VERSION 5.7 ;
  NOWIREEXTENSIONATPIN ON ;
  DIVIDERCHAR "/" ;
  BUSBITCHARS "[]" ;
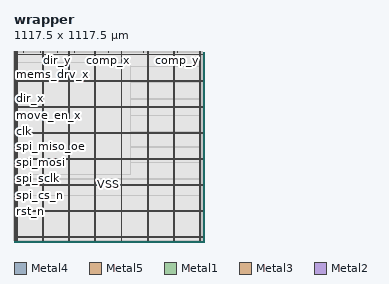
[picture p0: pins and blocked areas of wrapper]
MACRO wrapper
  CLASS BLOCK ;
  FOREIGN wrapper ;
  ORIGIN 0.000 0.000 ;
  SIZE 1117.500 BY 1117.500 ;
  PIN VDD
    DIRECTION INOUT ;
    USE POWER ;
    PORT
      LAYER Metal4 ;
        RECT 15.520 11.460 17.120 1117.500 ;
    END
    PORT
      LAYER Metal4 ;
        RECT 169.120 11.460 170.720 1117.500 ;
    END
    PORT
      LAYER Metal4 ;
        RECT 322.720 11.460 324.320 1117.500 ;
    END
    PORT
      LAYER Metal4 ;
        RECT 476.320 11.460 477.920 1117.500 ;
    END
    PORT
      LAYER Metal4 ;
        RECT 629.920 11.460 631.520 1117.500 ;
    END
    PORT
      LAYER Metal4 ;
        RECT 783.520 11.460 785.120 1117.500 ;
    END
    PORT
      LAYER Metal4 ;
        RECT 937.120 11.460 938.720 1117.500 ;
    END
    PORT
      LAYER Metal4 ;
        RECT 1090.720 11.460 1092.320 1117.500 ;
    END
    PORT
      LAYER Metal5 ;
        RECT 0.000 27.610 1107.120 29.210 ;
    END
    PORT
      LAYER Metal5 ;
        RECT 0.000 180.790 1107.120 182.390 ;
    END
    PORT
      LAYER Metal5 ;
        RECT 0.000 333.970 1107.120 335.570 ;
    END
    PORT
      LAYER Metal5 ;
        RECT 0.000 487.150 1107.120 488.750 ;
    END
    PORT
      LAYER Metal5 ;
        RECT 0.000 640.330 1107.120 641.930 ;
    END
    PORT
      LAYER Metal5 ;
        RECT 0.000 793.510 1107.120 795.110 ;
    END
    PORT
      LAYER Metal5 ;
        RECT 0.000 946.690 1107.120 948.290 ;
    END
    PORT
      LAYER Metal5 ;
        RECT 0.000 1099.870 1107.120 1101.470 ;
    END
    PORT
      LAYER Metal1 ;
        RECT 0.000 15.380 15.670 15.980 ;
    END
    PORT
      LAYER Metal1 ;
        RECT 0.000 23.220 15.670 23.820 ;
    END
    PORT
      LAYER Metal1 ;
        RECT 0.000 31.060 15.670 31.660 ;
    END
    PORT
      LAYER Metal1 ;
        RECT 0.000 38.900 15.670 39.500 ;
    END
    PORT
      LAYER Metal1 ;
        RECT 0.000 46.740 15.670 47.340 ;
    END
    PORT
      LAYER Metal1 ;
        RECT 0.000 54.580 15.670 55.180 ;
    END
    PORT
      LAYER Metal1 ;
        RECT 0.000 62.420 15.670 63.020 ;
    END
    PORT
      LAYER Metal1 ;
        RECT 0.000 70.260 15.670 70.860 ;
    END
    PORT
      LAYER Metal1 ;
        RECT 0.000 78.100 15.670 78.700 ;
    END
    PORT
      LAYER Metal1 ;
        RECT 0.000 85.940 15.670 86.540 ;
    END
    PORT
      LAYER Metal1 ;
        RECT 0.000 93.780 15.670 94.380 ;
    END
    PORT
      LAYER Metal1 ;
        RECT 0.000 101.620 15.670 102.220 ;
    END
    PORT
      LAYER Metal1 ;
        RECT 0.000 109.460 15.670 110.060 ;
    END
    PORT
      LAYER Metal1 ;
        RECT 0.000 117.300 15.670 117.900 ;
    END
    PORT
      LAYER Metal1 ;
        RECT 0.000 125.140 15.670 125.740 ;
    END
    PORT
      LAYER Metal1 ;
        RECT 0.000 132.980 15.670 133.580 ;
    END
    PORT
      LAYER Metal1 ;
        RECT 0.000 140.820 15.670 141.420 ;
    END
    PORT
      LAYER Metal1 ;
        RECT 0.000 148.660 15.670 149.260 ;
    END
    PORT
      LAYER Metal1 ;
        RECT 0.000 156.500 15.670 157.100 ;
    END
    PORT
      LAYER Metal1 ;
        RECT 0.000 164.340 15.670 164.940 ;
    END
    PORT
      LAYER Metal1 ;
        RECT 0.000 172.180 15.670 172.780 ;
    END
    PORT
      LAYER Metal1 ;
        RECT 0.000 180.020 15.670 180.620 ;
    END
    PORT
      LAYER Metal1 ;
        RECT 0.000 187.860 15.670 188.460 ;
    END
    PORT
      LAYER Metal1 ;
        RECT 0.000 195.700 15.670 196.300 ;
    END
    PORT
      LAYER Metal1 ;
        RECT 0.000 203.540 15.670 204.140 ;
    END
    PORT
      LAYER Metal1 ;
        RECT 0.000 211.380 15.670 211.980 ;
    END
    PORT
      LAYER Metal1 ;
        RECT 0.000 219.220 15.670 219.820 ;
    END
    PORT
      LAYER Metal1 ;
        RECT 0.000 227.060 15.670 227.660 ;
    END
    PORT
      LAYER Metal1 ;
        RECT 0.000 234.900 15.670 235.500 ;
    END
    PORT
      LAYER Metal1 ;
        RECT 0.000 242.740 15.670 243.340 ;
    END
    PORT
      LAYER Metal1 ;
        RECT 0.000 250.580 15.670 251.180 ;
    END
    PORT
      LAYER Metal1 ;
        RECT 0.000 258.420 15.670 259.020 ;
    END
    PORT
      LAYER Metal1 ;
        RECT 0.000 266.260 15.670 266.860 ;
    END
    PORT
      LAYER Metal1 ;
        RECT 0.000 274.100 15.670 274.700 ;
    END
    PORT
      LAYER Metal1 ;
        RECT 0.000 281.940 15.670 282.540 ;
    END
    PORT
      LAYER Metal1 ;
        RECT 0.000 289.780 15.670 290.380 ;
    END
    PORT
      LAYER Metal1 ;
        RECT 0.000 297.620 15.670 298.220 ;
    END
    PORT
      LAYER Metal1 ;
        RECT 0.000 305.460 15.670 306.060 ;
    END
    PORT
      LAYER Metal1 ;
        RECT 0.000 313.300 15.670 313.900 ;
    END
    PORT
      LAYER Metal1 ;
        RECT 0.000 321.140 15.670 321.740 ;
    END
    PORT
      LAYER Metal1 ;
        RECT 0.000 328.980 15.670 329.580 ;
    END
    PORT
      LAYER Metal1 ;
        RECT 0.000 336.820 15.670 337.420 ;
    END
    PORT
      LAYER Metal1 ;
        RECT 0.000 344.660 15.670 345.260 ;
    END
    PORT
      LAYER Metal1 ;
        RECT 0.000 352.500 15.670 353.100 ;
    END
    PORT
      LAYER Metal1 ;
        RECT 0.000 360.340 15.670 360.940 ;
    END
    PORT
      LAYER Metal1 ;
        RECT 0.000 368.180 11.090 368.780 ;
    END
    PORT
      LAYER Metal1 ;
        RECT 0.000 376.020 15.670 376.620 ;
    END
    PORT
      LAYER Metal1 ;
        RECT 0.000 383.860 15.670 384.460 ;
    END
    PORT
      LAYER Metal1 ;
        RECT 0.000 391.700 15.670 392.300 ;
    END
    PORT
      LAYER Metal1 ;
        RECT 0.000 399.540 15.670 400.140 ;
    END
    PORT
      LAYER Metal1 ;
        RECT 0.000 407.380 15.670 407.980 ;
    END
    PORT
      LAYER Metal1 ;
        RECT 0.000 415.220 15.670 415.820 ;
    END
    PORT
      LAYER Metal1 ;
        RECT 0.000 423.060 15.670 423.660 ;
    END
    PORT
      LAYER Metal1 ;
        RECT 0.000 430.900 15.670 431.500 ;
    END
    PORT
      LAYER Metal1 ;
        RECT 0.000 438.740 15.670 439.340 ;
    END
    PORT
      LAYER Metal1 ;
        RECT 0.000 446.580 15.670 447.180 ;
    END
    PORT
      LAYER Metal1 ;
        RECT 0.000 454.420 15.670 455.020 ;
    END
    PORT
      LAYER Metal1 ;
        RECT 0.000 462.260 15.670 462.860 ;
    END
    PORT
      LAYER Metal1 ;
        RECT 0.000 470.100 15.670 470.700 ;
    END
    PORT
      LAYER Metal1 ;
        RECT 0.000 477.940 15.670 478.540 ;
    END
    PORT
      LAYER Metal1 ;
        RECT 0.000 485.780 15.670 486.380 ;
    END
    PORT
      LAYER Metal1 ;
        RECT 0.000 493.620 15.670 494.220 ;
    END
    PORT
      LAYER Metal1 ;
        RECT 0.000 501.460 15.670 502.060 ;
    END
    PORT
      LAYER Metal1 ;
        RECT 0.000 509.300 15.670 509.900 ;
    END
    PORT
      LAYER Metal1 ;
        RECT 0.000 517.140 15.670 517.740 ;
    END
    PORT
      LAYER Metal1 ;
        RECT 0.000 524.980 15.670 525.580 ;
    END
    PORT
      LAYER Metal1 ;
        RECT 0.000 532.820 15.670 533.420 ;
    END
    PORT
      LAYER Metal1 ;
        RECT 0.000 540.660 15.670 541.260 ;
    END
    PORT
      LAYER Metal1 ;
        RECT 0.000 548.500 15.670 549.100 ;
    END
    PORT
      LAYER Metal1 ;
        RECT 0.000 556.340 15.670 556.940 ;
    END
    PORT
      LAYER Metal1 ;
        RECT 0.000 564.180 15.670 564.780 ;
    END
    PORT
      LAYER Metal1 ;
        RECT 0.000 572.020 15.670 572.620 ;
    END
    PORT
      LAYER Metal1 ;
        RECT 0.000 579.860 15.670 580.460 ;
    END
    PORT
      LAYER Metal1 ;
        RECT 0.000 587.700 15.670 588.300 ;
    END
    PORT
      LAYER Metal1 ;
        RECT 0.000 595.540 15.670 596.140 ;
    END
    PORT
      LAYER Metal1 ;
        RECT 0.000 603.380 15.670 603.980 ;
    END
    PORT
      LAYER Metal1 ;
        RECT 0.000 611.220 15.670 611.820 ;
    END
    PORT
      LAYER Metal1 ;
        RECT 0.000 619.060 15.670 619.660 ;
    END
    PORT
      LAYER Metal1 ;
        RECT 0.000 626.900 15.670 627.500 ;
    END
    PORT
      LAYER Metal1 ;
        RECT 0.000 634.740 15.670 635.340 ;
    END
    PORT
      LAYER Metal1 ;
        RECT 0.000 642.580 15.670 643.180 ;
    END
    PORT
      LAYER Metal1 ;
        RECT 0.000 650.420 15.670 651.020 ;
    END
    PORT
      LAYER Metal1 ;
        RECT 0.000 658.260 15.670 658.860 ;
    END
    PORT
      LAYER Metal1 ;
        RECT 0.000 666.100 15.670 666.700 ;
    END
    PORT
      LAYER Metal1 ;
        RECT 0.000 673.940 15.670 674.540 ;
    END
    PORT
      LAYER Metal1 ;
        RECT 0.000 681.780 15.670 682.380 ;
    END
    PORT
      LAYER Metal1 ;
        RECT 0.000 689.620 15.670 690.220 ;
    END
    PORT
      LAYER Metal1 ;
        RECT 0.000 697.460 15.670 698.060 ;
    END
    PORT
      LAYER Metal1 ;
        RECT 0.000 705.300 15.670 705.900 ;
    END
    PORT
      LAYER Metal1 ;
        RECT 0.000 713.140 15.670 713.740 ;
    END
    PORT
      LAYER Metal1 ;
        RECT 0.000 720.980 15.670 721.580 ;
    END
    PORT
      LAYER Metal1 ;
        RECT 0.000 728.820 15.670 729.420 ;
    END
    PORT
      LAYER Metal1 ;
        RECT 0.000 736.660 15.670 737.260 ;
    END
    PORT
      LAYER Metal1 ;
        RECT 0.000 744.500 15.670 745.100 ;
    END
    PORT
      LAYER Metal1 ;
        RECT 0.000 752.340 15.670 752.940 ;
    END
    PORT
      LAYER Metal1 ;
        RECT 0.000 760.180 15.670 760.780 ;
    END
    PORT
      LAYER Metal1 ;
        RECT 0.000 768.020 15.670 768.620 ;
    END
    PORT
      LAYER Metal1 ;
        RECT 0.000 775.860 15.670 776.460 ;
    END
    PORT
      LAYER Metal1 ;
        RECT 0.000 783.700 15.670 784.300 ;
    END
    PORT
      LAYER Metal1 ;
        RECT 0.000 791.540 15.670 792.140 ;
    END
    PORT
      LAYER Metal1 ;
        RECT 0.000 799.380 15.670 799.980 ;
    END
    PORT
      LAYER Metal1 ;
        RECT 0.000 807.220 15.670 807.820 ;
    END
    PORT
      LAYER Metal1 ;
        RECT 0.000 815.060 15.670 815.660 ;
    END
    PORT
      LAYER Metal1 ;
        RECT 0.000 822.900 15.670 823.500 ;
    END
    PORT
      LAYER Metal1 ;
        RECT 0.000 830.740 15.670 831.340 ;
    END
    PORT
      LAYER Metal1 ;
        RECT 0.000 838.580 15.670 839.180 ;
    END
    PORT
      LAYER Metal1 ;
        RECT 0.000 846.420 15.670 847.020 ;
    END
    PORT
      LAYER Metal1 ;
        RECT 0.000 854.260 15.670 854.860 ;
    END
    PORT
      LAYER Metal1 ;
        RECT 0.000 862.100 15.670 862.700 ;
    END
    PORT
      LAYER Metal1 ;
        RECT 0.000 869.940 15.670 870.540 ;
    END
    PORT
      LAYER Metal1 ;
        RECT 0.000 877.780 15.670 878.380 ;
    END
    PORT
      LAYER Metal1 ;
        RECT 0.000 885.620 15.670 886.220 ;
    END
    PORT
      LAYER Metal1 ;
        RECT 0.000 893.460 15.670 894.060 ;
    END
    PORT
      LAYER Metal1 ;
        RECT 0.000 901.300 15.670 901.900 ;
    END
    PORT
      LAYER Metal1 ;
        RECT 0.000 909.140 15.670 909.740 ;
    END
    PORT
      LAYER Metal1 ;
        RECT 0.000 916.980 15.670 917.580 ;
    END
    PORT
      LAYER Metal1 ;
        RECT 0.000 924.820 15.670 925.420 ;
    END
    PORT
      LAYER Metal1 ;
        RECT 0.000 932.660 15.670 933.260 ;
    END
    PORT
      LAYER Metal1 ;
        RECT 0.000 940.500 15.670 941.100 ;
    END
    PORT
      LAYER Metal1 ;
        RECT 0.000 948.340 15.670 948.940 ;
    END
    PORT
      LAYER Metal1 ;
        RECT 0.000 956.180 15.670 956.780 ;
    END
    PORT
      LAYER Metal1 ;
        RECT 0.000 964.020 15.670 964.620 ;
    END
    PORT
      LAYER Metal1 ;
        RECT 0.000 971.860 15.670 972.460 ;
    END
    PORT
      LAYER Metal1 ;
        RECT 0.000 979.700 15.670 980.300 ;
    END
    PORT
      LAYER Metal1 ;
        RECT 0.000 987.540 15.670 988.140 ;
    END
    PORT
      LAYER Metal1 ;
        RECT 0.000 995.380 15.670 995.980 ;
    END
    PORT
      LAYER Metal1 ;
        RECT 0.000 1003.220 15.670 1003.820 ;
    END
    PORT
      LAYER Metal1 ;
        RECT 0.000 1011.060 15.670 1011.660 ;
    END
    PORT
      LAYER Metal1 ;
        RECT 0.000 1018.900 15.670 1019.500 ;
    END
    PORT
      LAYER Metal1 ;
        RECT 0.000 1026.740 15.670 1027.340 ;
    END
    PORT
      LAYER Metal1 ;
        RECT 0.000 1034.580 15.670 1035.180 ;
    END
    PORT
      LAYER Metal1 ;
        RECT 0.000 1042.420 15.670 1043.020 ;
    END
    PORT
      LAYER Metal1 ;
        RECT 0.000 1050.260 15.670 1050.860 ;
    END
    PORT
      LAYER Metal1 ;
        RECT 0.000 1058.100 15.670 1058.700 ;
    END
    PORT
      LAYER Metal1 ;
        RECT 0.000 1065.940 15.670 1066.540 ;
    END
    PORT
      LAYER Metal1 ;
        RECT 0.000 1073.780 15.670 1074.380 ;
    END
    PORT
      LAYER Metal1 ;
        RECT 0.000 1081.620 15.670 1082.220 ;
    END
    PORT
      LAYER Metal1 ;
        RECT 0.000 1089.460 15.670 1090.060 ;
    END
    PORT
      LAYER Metal1 ;
        RECT 0.000 1097.300 15.670 1097.900 ;
    END
    PORT
      LAYER Metal1 ;
        RECT 0.000 1105.140 15.670 1105.740 ;
    END
    PORT
      LAYER Metal1 ;
        RECT 0.000 1112.980 15.670 1113.580 ;
    END
  END VDD
  PIN VSS
    DIRECTION INOUT ;
    USE GROUND ;
    PORT
      LAYER Metal4 ;
        RECT 18.820 11.460 20.420 1117.500 ;
    END
    PORT
      LAYER Metal4 ;
        RECT 172.420 11.460 174.020 1117.500 ;
    END
    PORT
      LAYER Metal4 ;
        RECT 326.020 11.460 327.620 1117.500 ;
    END
    PORT
      LAYER Metal4 ;
        RECT 479.620 11.460 481.220 1117.500 ;
    END
    PORT
      LAYER Metal4 ;
        RECT 633.220 11.460 634.820 1117.500 ;
    END
    PORT
      LAYER Metal4 ;
        RECT 786.820 11.460 788.420 1117.500 ;
    END
    PORT
      LAYER Metal4 ;
        RECT 940.420 11.460 942.020 1117.500 ;
    END
    PORT
      LAYER Metal4 ;
        RECT 1094.020 11.460 1095.620 1117.500 ;
    END
    PORT
      LAYER Metal5 ;
        RECT 0.000 30.910 1107.120 32.510 ;
    END
    PORT
      LAYER Metal5 ;
        RECT 0.000 184.090 1107.120 185.690 ;
    END
    PORT
      LAYER Metal5 ;
        RECT 0.000 337.270 1107.120 338.870 ;
    END
    PORT
      LAYER Metal5 ;
        RECT 0.000 490.450 1107.120 492.050 ;
    END
    PORT
      LAYER Metal5 ;
        RECT 0.000 643.630 1107.120 645.230 ;
    END
    PORT
      LAYER Metal5 ;
        RECT 0.000 796.810 1107.120 798.410 ;
    END
    PORT
      LAYER Metal5 ;
        RECT 0.000 949.990 1107.120 951.590 ;
    END
    PORT
      LAYER Metal5 ;
        RECT 0.000 1103.170 1107.120 1104.770 ;
    END
    PORT
      LAYER Metal1 ;
        RECT 0.000 11.460 18.970 12.060 ;
    END
    PORT
      LAYER Metal1 ;
        RECT 0.000 19.300 18.970 19.900 ;
    END
    PORT
      LAYER Metal1 ;
        RECT 0.000 27.140 18.970 27.740 ;
    END
    PORT
      LAYER Metal1 ;
        RECT 0.000 34.980 18.970 35.580 ;
    END
    PORT
      LAYER Metal1 ;
        RECT 0.000 42.820 18.970 43.420 ;
    END
    PORT
      LAYER Metal1 ;
        RECT 0.000 50.660 18.970 51.260 ;
    END
    PORT
      LAYER Metal1 ;
        RECT 0.000 58.500 18.970 59.100 ;
    END
    PORT
      LAYER Metal1 ;
        RECT 0.000 66.340 18.970 66.940 ;
    END
    PORT
      LAYER Metal1 ;
        RECT 0.000 74.180 18.970 74.780 ;
    END
    PORT
      LAYER Metal1 ;
        RECT 0.000 82.020 18.970 82.620 ;
    END
    PORT
      LAYER Metal1 ;
        RECT 0.000 89.860 18.970 90.460 ;
    END
    PORT
      LAYER Metal1 ;
        RECT 0.000 97.700 18.970 98.300 ;
    END
    PORT
      LAYER Metal1 ;
        RECT 0.000 105.540 18.970 106.140 ;
    END
    PORT
      LAYER Metal1 ;
        RECT 0.000 113.380 18.970 113.980 ;
    END
    PORT
      LAYER Metal1 ;
        RECT 0.000 121.220 18.970 121.820 ;
    END
    PORT
      LAYER Metal1 ;
        RECT 0.000 129.060 18.970 129.660 ;
    END
    PORT
      LAYER Metal1 ;
        RECT 0.000 136.900 18.970 137.500 ;
    END
    PORT
      LAYER Metal1 ;
        RECT 0.000 144.740 18.970 145.340 ;
    END
    PORT
      LAYER Metal1 ;
        RECT 0.000 152.580 18.970 153.180 ;
    END
    PORT
      LAYER Metal1 ;
        RECT 0.000 160.420 18.970 161.020 ;
    END
    PORT
      LAYER Metal1 ;
        RECT 0.000 168.260 18.970 168.860 ;
    END
    PORT
      LAYER Metal1 ;
        RECT 0.000 176.100 18.970 176.700 ;
    END
    PORT
      LAYER Metal1 ;
        RECT 0.000 183.940 18.970 184.540 ;
    END
    PORT
      LAYER Metal1 ;
        RECT 0.000 191.780 18.970 192.380 ;
    END
    PORT
      LAYER Metal1 ;
        RECT 0.000 199.620 18.970 200.220 ;
    END
    PORT
      LAYER Metal1 ;
        RECT 0.000 207.460 18.970 208.060 ;
    END
    PORT
      LAYER Metal1 ;
        RECT 0.000 215.300 18.970 215.900 ;
    END
    PORT
      LAYER Metal1 ;
        RECT 0.000 223.140 18.970 223.740 ;
    END
    PORT
      LAYER Metal1 ;
        RECT 0.000 230.980 18.970 231.580 ;
    END
    PORT
      LAYER Metal1 ;
        RECT 0.000 238.820 18.970 239.420 ;
    END
    PORT
      LAYER Metal1 ;
        RECT 0.000 246.660 18.970 247.260 ;
    END
    PORT
      LAYER Metal1 ;
        RECT 0.000 254.500 18.970 255.100 ;
    END
    PORT
      LAYER Metal1 ;
        RECT 0.000 262.340 18.970 262.940 ;
    END
    PORT
      LAYER Metal1 ;
        RECT 0.000 270.180 18.970 270.780 ;
    END
    PORT
      LAYER Metal1 ;
        RECT 0.000 278.020 18.970 278.620 ;
    END
    PORT
      LAYER Metal1 ;
        RECT 0.000 285.860 18.970 286.460 ;
    END
    PORT
      LAYER Metal1 ;
        RECT 0.000 293.700 18.970 294.300 ;
    END
    PORT
      LAYER Metal1 ;
        RECT 0.000 301.540 18.970 302.140 ;
    END
    PORT
      LAYER Metal1 ;
        RECT 0.000 309.380 18.970 309.980 ;
    END
    PORT
      LAYER Metal1 ;
        RECT 0.000 317.220 18.970 317.820 ;
    END
    PORT
      LAYER Metal1 ;
        RECT 0.000 325.060 18.970 325.660 ;
    END
    PORT
      LAYER Metal1 ;
        RECT 0.000 332.900 18.970 333.500 ;
    END
    PORT
      LAYER Metal1 ;
        RECT 0.000 340.740 18.970 341.340 ;
    END
    PORT
      LAYER Metal1 ;
        RECT 0.000 348.580 18.970 349.180 ;
    END
    PORT
      LAYER Metal1 ;
        RECT 0.000 356.420 18.970 357.020 ;
    END
    PORT
      LAYER Metal1 ;
        RECT 0.000 364.260 18.970 364.860 ;
    END
    PORT
      LAYER Metal1 ;
        RECT 0.000 372.100 18.970 372.700 ;
    END
    PORT
      LAYER Metal1 ;
        RECT 0.000 379.940 18.970 380.540 ;
    END
    PORT
      LAYER Metal1 ;
        RECT 0.000 387.780 18.970 388.380 ;
    END
    PORT
      LAYER Metal1 ;
        RECT 0.000 395.620 18.970 396.220 ;
    END
    PORT
      LAYER Metal1 ;
        RECT 0.000 403.460 18.970 404.060 ;
    END
    PORT
      LAYER Metal1 ;
        RECT 0.000 411.300 18.970 411.900 ;
    END
    PORT
      LAYER Metal1 ;
        RECT 0.000 419.140 18.970 419.740 ;
    END
    PORT
      LAYER Metal1 ;
        RECT 0.000 426.980 18.970 427.580 ;
    END
    PORT
      LAYER Metal1 ;
        RECT 0.000 434.820 18.970 435.420 ;
    END
    PORT
      LAYER Metal1 ;
        RECT 0.000 442.660 18.970 443.260 ;
    END
    PORT
      LAYER Metal1 ;
        RECT 0.000 450.500 18.970 451.100 ;
    END
    PORT
      LAYER Metal1 ;
        RECT 0.000 458.340 18.970 458.940 ;
    END
    PORT
      LAYER Metal1 ;
        RECT 0.000 466.180 18.970 466.780 ;
    END
    PORT
      LAYER Metal1 ;
        RECT 0.000 474.020 18.970 474.620 ;
    END
    PORT
      LAYER Metal1 ;
        RECT 0.000 481.860 18.970 482.460 ;
    END
    PORT
      LAYER Metal1 ;
        RECT 0.000 489.700 18.970 490.300 ;
    END
    PORT
      LAYER Metal1 ;
        RECT 0.000 497.540 18.970 498.140 ;
    END
    PORT
      LAYER Metal1 ;
        RECT 0.000 505.380 18.970 505.980 ;
    END
    PORT
      LAYER Metal1 ;
        RECT 0.000 513.220 18.970 513.820 ;
    END
    PORT
      LAYER Metal1 ;
        RECT 0.000 521.060 18.970 521.660 ;
    END
    PORT
      LAYER Metal1 ;
        RECT 0.000 528.900 18.970 529.500 ;
    END
    PORT
      LAYER Metal1 ;
        RECT 0.000 536.740 18.970 537.340 ;
    END
    PORT
      LAYER Metal1 ;
        RECT 0.000 544.580 18.970 545.180 ;
    END
    PORT
      LAYER Metal1 ;
        RECT 0.000 552.420 18.970 553.020 ;
    END
    PORT
      LAYER Metal1 ;
        RECT 0.000 560.260 18.970 560.860 ;
    END
    PORT
      LAYER Metal1 ;
        RECT 0.000 568.100 18.970 568.700 ;
    END
    PORT
      LAYER Metal1 ;
        RECT 0.000 575.940 18.970 576.540 ;
    END
    PORT
      LAYER Metal1 ;
        RECT 0.000 583.780 18.970 584.380 ;
    END
    PORT
      LAYER Metal1 ;
        RECT 0.000 591.620 18.970 592.220 ;
    END
    PORT
      LAYER Metal1 ;
        RECT 0.000 599.460 18.970 600.060 ;
    END
    PORT
      LAYER Metal1 ;
        RECT 0.000 607.300 18.970 607.900 ;
    END
    PORT
      LAYER Metal1 ;
        RECT 0.000 615.140 18.970 615.740 ;
    END
    PORT
      LAYER Metal1 ;
        RECT 0.000 622.980 18.970 623.580 ;
    END
    PORT
      LAYER Metal1 ;
        RECT 0.000 630.820 18.970 631.420 ;
    END
    PORT
      LAYER Metal1 ;
        RECT 0.000 638.660 18.970 639.260 ;
    END
    PORT
      LAYER Metal1 ;
        RECT 0.000 646.500 18.970 647.100 ;
    END
    PORT
      LAYER Metal1 ;
        RECT 0.000 654.340 18.970 654.940 ;
    END
    PORT
      LAYER Metal1 ;
        RECT 0.000 662.180 18.970 662.780 ;
    END
    PORT
      LAYER Metal1 ;
        RECT 0.000 670.020 18.970 670.620 ;
    END
    PORT
      LAYER Metal1 ;
        RECT 0.000 677.860 18.970 678.460 ;
    END
    PORT
      LAYER Metal1 ;
        RECT 0.000 685.700 18.970 686.300 ;
    END
    PORT
      LAYER Metal1 ;
        RECT 0.000 693.540 18.970 694.140 ;
    END
    PORT
      LAYER Metal1 ;
        RECT 0.000 701.380 18.970 701.980 ;
    END
    PORT
      LAYER Metal1 ;
        RECT 0.000 709.220 18.970 709.820 ;
    END
    PORT
      LAYER Metal1 ;
        RECT 0.000 717.060 18.970 717.660 ;
    END
    PORT
      LAYER Metal1 ;
        RECT 0.000 724.900 18.970 725.500 ;
    END
    PORT
      LAYER Metal1 ;
        RECT 0.000 732.740 18.970 733.340 ;
    END
    PORT
      LAYER Metal1 ;
        RECT 0.000 740.580 18.970 741.180 ;
    END
    PORT
      LAYER Metal1 ;
        RECT 0.000 748.420 18.970 749.020 ;
    END
    PORT
      LAYER Metal1 ;
        RECT 0.000 756.260 18.970 756.860 ;
    END
    PORT
      LAYER Metal1 ;
        RECT 0.000 764.100 18.970 764.700 ;
    END
    PORT
      LAYER Metal1 ;
        RECT 0.000 771.940 18.970 772.540 ;
    END
    PORT
      LAYER Metal1 ;
        RECT 0.000 779.780 18.970 780.380 ;
    END
    PORT
      LAYER Metal1 ;
        RECT 0.000 787.620 18.970 788.220 ;
    END
    PORT
      LAYER Metal1 ;
        RECT 0.000 795.460 18.970 796.060 ;
    END
    PORT
      LAYER Metal1 ;
        RECT 0.000 803.300 18.970 803.900 ;
    END
    PORT
      LAYER Metal1 ;
        RECT 0.000 811.140 18.970 811.740 ;
    END
    PORT
      LAYER Metal1 ;
        RECT 0.000 818.980 18.970 819.580 ;
    END
    PORT
      LAYER Metal1 ;
        RECT 0.000 826.820 18.970 827.420 ;
    END
    PORT
      LAYER Metal1 ;
        RECT 0.000 834.660 18.970 835.260 ;
    END
    PORT
      LAYER Metal1 ;
        RECT 0.000 842.500 18.970 843.100 ;
    END
    PORT
      LAYER Metal1 ;
        RECT 0.000 850.340 18.970 850.940 ;
    END
    PORT
      LAYER Metal1 ;
        RECT 0.000 858.180 18.970 858.780 ;
    END
    PORT
      LAYER Metal1 ;
        RECT 0.000 866.020 18.970 866.620 ;
    END
    PORT
      LAYER Metal1 ;
        RECT 0.000 873.860 18.970 874.460 ;
    END
    PORT
      LAYER Metal1 ;
        RECT 0.000 881.700 18.970 882.300 ;
    END
    PORT
      LAYER Metal1 ;
        RECT 0.000 889.540 18.970 890.140 ;
    END
    PORT
      LAYER Metal1 ;
        RECT 0.000 897.380 18.970 897.980 ;
    END
    PORT
      LAYER Metal1 ;
        RECT 0.000 905.220 18.970 905.820 ;
    END
    PORT
      LAYER Metal1 ;
        RECT 0.000 913.060 18.970 913.660 ;
    END
    PORT
      LAYER Metal1 ;
        RECT 0.000 920.900 18.970 921.500 ;
    END
    PORT
      LAYER Metal1 ;
        RECT 0.000 928.740 18.970 929.340 ;
    END
    PORT
      LAYER Metal1 ;
        RECT 0.000 936.580 18.970 937.180 ;
    END
    PORT
      LAYER Metal1 ;
        RECT 0.000 944.420 18.970 945.020 ;
    END
    PORT
      LAYER Metal1 ;
        RECT 0.000 952.260 18.970 952.860 ;
    END
    PORT
      LAYER Metal1 ;
        RECT 0.000 960.100 18.970 960.700 ;
    END
    PORT
      LAYER Metal1 ;
        RECT 0.000 967.940 18.970 968.540 ;
    END
    PORT
      LAYER Metal1 ;
        RECT 0.000 975.780 18.970 976.380 ;
    END
    PORT
      LAYER Metal1 ;
        RECT 0.000 983.620 18.970 984.220 ;
    END
    PORT
      LAYER Metal1 ;
        RECT 0.000 991.460 18.970 992.060 ;
    END
    PORT
      LAYER Metal1 ;
        RECT 0.000 999.300 18.970 999.900 ;
    END
    PORT
      LAYER Metal1 ;
        RECT 0.000 1007.140 18.970 1007.740 ;
    END
    PORT
      LAYER Metal1 ;
        RECT 0.000 1014.980 18.970 1015.580 ;
    END
    PORT
      LAYER Metal1 ;
        RECT 0.000 1022.820 18.970 1023.420 ;
    END
    PORT
      LAYER Metal1 ;
        RECT 0.000 1030.660 18.970 1031.260 ;
    END
    PORT
      LAYER Metal1 ;
        RECT 0.000 1038.500 18.970 1039.100 ;
    END
    PORT
      LAYER Metal1 ;
        RECT 0.000 1046.340 18.970 1046.940 ;
    END
    PORT
      LAYER Metal1 ;
        RECT 0.000 1054.180 18.970 1054.780 ;
    END
    PORT
      LAYER Metal1 ;
        RECT 0.000 1062.020 18.970 1062.620 ;
    END
    PORT
      LAYER Metal1 ;
        RECT 0.000 1069.860 18.970 1070.460 ;
    END
    PORT
      LAYER Metal1 ;
        RECT 0.000 1077.700 18.970 1078.300 ;
    END
    PORT
      LAYER Metal1 ;
        RECT 0.000 1085.540 18.970 1086.140 ;
    END
    PORT
      LAYER Metal1 ;
        RECT 0.000 1093.380 18.970 1093.980 ;
    END
    PORT
      LAYER Metal1 ;
        RECT 0.000 1101.220 18.970 1101.820 ;
    END
    PORT
      LAYER Metal1 ;
        RECT 0.000 1109.060 18.970 1109.660 ;
    END
    PORT
      LAYER Metal1 ;
        RECT 0.000 1116.900 18.970 1117.500 ;
    END
  END VSS
  PIN clk
    DIRECTION INPUT ;
    USE SIGNAL ;
    ANTENNAGATEAREA 4.738000 ;
    ANTENNADIFFAREA 0.410400 ;
    PORT
      LAYER Metal3 ;
        RECT 0.000 650.720 0.560 651.280 ;
    END
  END clk
  PIN comp_x
    DIRECTION INPUT ;
    USE SIGNAL ;
    ANTENNAGATEAREA 0.498500 ;
    ANTENNADIFFAREA 0.410400 ;
    PORT
      LAYER Metal2 ;
        RECT 557.760 1116.940 558.320 1117.500 ;
    END
  END comp_x
  PIN comp_y
    DIRECTION INPUT ;
    USE SIGNAL ;
    ANTENNAGATEAREA 1.102000 ;
    ANTENNADIFFAREA 0.410400 ;
    PORT
      LAYER Metal2 ;
        RECT 960.960 1116.940 961.520 1117.500 ;
    END
  END comp_y
  PIN dir_x
    DIRECTION OUTPUT ;
    USE SIGNAL ;
    ANTENNADIFFAREA 1.182800 ;
    PORT
      LAYER Metal3 ;
        RECT 0.000 841.120 0.560 841.680 ;
    END
  END dir_x
  PIN dir_y
    DIRECTION OUTPUT ;
    USE SIGNAL ;
    ANTENNADIFFAREA 1.182800 ;
    PORT
      LAYER Metal2 ;
        RECT 255.360 1116.940 255.920 1117.500 ;
    END
  END dir_y
  PIN mems_drv_x
    DIRECTION OUTPUT ;
    USE SIGNAL ;
    ANTENNADIFFAREA 1.182800 ;
    PORT
      LAYER Metal3 ;
        RECT 0.000 1031.520 0.560 1032.080 ;
    END
  END mems_drv_x
  PIN mems_drv_y
    DIRECTION OUTPUT ;
    USE SIGNAL ;
    ANTENNADIFFAREA 1.182800 ;
    PORT
      LAYER Metal2 ;
        RECT 53.760 1116.940 54.320 1117.500 ;
    END
  END mems_drv_y
  PIN move_en_x
    DIRECTION OUTPUT ;
    USE SIGNAL ;
    ANTENNADIFFAREA 1.182800 ;
    PORT
      LAYER Metal3 ;
        RECT 0.000 745.920 0.560 746.480 ;
    END
  END move_en_x
  PIN move_en_y
    DIRECTION OUTPUT ;
    USE SIGNAL ;
    ANTENNADIFFAREA 1.182800 ;
    PORT
      LAYER Metal2 ;
        RECT 356.160 1116.940 356.720 1117.500 ;
    END
  END move_en_y
  PIN read_en
    DIRECTION OUTPUT ;
    USE SIGNAL ;
    ANTENNADIFFAREA 1.182800 ;
    PORT
      LAYER Metal2 ;
        RECT 759.360 1116.940 759.920 1117.500 ;
    END
  END read_en
  PIN ref_wave_x
    DIRECTION OUTPUT ;
    USE SIGNAL ;
    ANTENNADIFFAREA 1.182800 ;
    PORT
      LAYER Metal3 ;
        RECT 0.000 936.320 0.560 936.880 ;
    END
  END ref_wave_x
  PIN ref_wave_y
    DIRECTION OUTPUT ;
    USE SIGNAL ;
    ANTENNADIFFAREA 1.182800 ;
    PORT
      LAYER Metal2 ;
        RECT 154.560 1116.940 155.120 1117.500 ;
    END
  END ref_wave_y
  PIN rst_n
    DIRECTION INPUT ;
    USE SIGNAL ;
    ANTENNAGATEAREA 1.183000 ;
    ANTENNADIFFAREA 0.410400 ;
    PORT
      LAYER Metal3 ;
        RECT 0.000 180.320 0.560 180.880 ;
    END
  END rst_n
  PIN spi_cs_n
    DIRECTION INPUT ;
    USE SIGNAL ;
    ANTENNAGATEAREA 0.498500 ;
    ANTENNADIFFAREA 0.410400 ;
    PORT
      LAYER Metal3 ;
        RECT 0.000 275.520 0.560 276.080 ;
    END
  END spi_cs_n
  PIN spi_miso
    DIRECTION OUTPUT ;
    USE SIGNAL ;
    ANTENNADIFFAREA 1.182800 ;
    PORT
      LAYER Metal3 ;
        RECT 0.000 555.520 0.560 556.080 ;
    END
  END spi_miso
  PIN spi_miso_oe
    DIRECTION OUTPUT ;
    USE SIGNAL ;
    ANTENNADIFFAREA 1.182800 ;
    PORT
      LAYER Metal3 ;
        RECT 0.000 561.120 0.560 561.680 ;
    END
  END spi_miso_oe
  PIN spi_mosi
    DIRECTION INPUT ;
    USE SIGNAL ;
    ANTENNAGATEAREA 0.498500 ;
    ANTENNADIFFAREA 0.410400 ;
    PORT
      LAYER Metal3 ;
        RECT 0.000 465.920 0.560 466.480 ;
    END
  END spi_mosi
  PIN spi_sclk
    DIRECTION INPUT ;
    USE SIGNAL ;
    ANTENNAGATEAREA 0.498500 ;
    ANTENNADIFFAREA 0.410400 ;
    PORT
      LAYER Metal3 ;
        RECT 0.000 370.720 0.560 371.280 ;
    END
  END spi_sclk
  OBS
      LAYER Pwell ;
        RECT -0.430 1115.440 1107.550 1117.630 ;
      LAYER Nwell ;
        RECT -0.430 1111.120 1107.550 1115.440 ;
      LAYER Pwell ;
        RECT -0.430 1107.600 1107.550 1111.120 ;
      LAYER Nwell ;
        RECT -0.430 1103.280 1107.550 1107.600 ;
      LAYER Pwell ;
        RECT -0.430 1099.760 1107.550 1103.280 ;
      LAYER Nwell ;
        RECT -0.430 1095.440 1107.550 1099.760 ;
      LAYER Pwell ;
        RECT -0.430 1091.920 1107.550 1095.440 ;
      LAYER Nwell ;
        RECT -0.430 1087.600 1107.550 1091.920 ;
      LAYER Pwell ;
        RECT -0.430 1084.080 1107.550 1087.600 ;
      LAYER Nwell ;
        RECT -0.430 1079.760 1107.550 1084.080 ;
      LAYER Pwell ;
        RECT -0.430 1076.240 1107.550 1079.760 ;
      LAYER Nwell ;
        RECT -0.430 1071.920 1107.550 1076.240 ;
      LAYER Pwell ;
        RECT -0.430 1068.400 1107.550 1071.920 ;
      LAYER Nwell ;
        RECT -0.430 1064.080 1107.550 1068.400 ;
      LAYER Pwell ;
        RECT -0.430 1060.560 1107.550 1064.080 ;
      LAYER Nwell ;
        RECT -0.430 1056.240 1107.550 1060.560 ;
      LAYER Pwell ;
        RECT -0.430 1052.720 1107.550 1056.240 ;
      LAYER Nwell ;
        RECT -0.430 1048.400 1107.550 1052.720 ;
      LAYER Pwell ;
        RECT -0.430 1044.880 1107.550 1048.400 ;
      LAYER Nwell ;
        RECT -0.430 1040.560 1107.550 1044.880 ;
      LAYER Pwell ;
        RECT -0.430 1037.040 1107.550 1040.560 ;
      LAYER Nwell ;
        RECT -0.430 1032.720 1107.550 1037.040 ;
      LAYER Pwell ;
        RECT -0.430 1029.200 1107.550 1032.720 ;
      LAYER Nwell ;
        RECT -0.430 1024.880 1107.550 1029.200 ;
      LAYER Pwell ;
        RECT -0.430 1021.360 1107.550 1024.880 ;
      LAYER Nwell ;
        RECT -0.430 1017.040 1107.550 1021.360 ;
      LAYER Pwell ;
        RECT -0.430 1013.520 1107.550 1017.040 ;
      LAYER Nwell ;
        RECT -0.430 1009.200 1107.550 1013.520 ;
      LAYER Pwell ;
        RECT -0.430 1005.680 1107.550 1009.200 ;
      LAYER Nwell ;
        RECT -0.430 1001.360 1107.550 1005.680 ;
      LAYER Pwell ;
        RECT -0.430 997.840 1107.550 1001.360 ;
      LAYER Nwell ;
        RECT -0.430 993.520 1107.550 997.840 ;
      LAYER Pwell ;
        RECT -0.430 990.000 1107.550 993.520 ;
      LAYER Nwell ;
        RECT -0.430 985.680 1107.550 990.000 ;
      LAYER Pwell ;
        RECT -0.430 982.160 1107.550 985.680 ;
      LAYER Nwell ;
        RECT -0.430 977.840 1107.550 982.160 ;
      LAYER Pwell ;
        RECT -0.430 974.320 1107.550 977.840 ;
      LAYER Nwell ;
        RECT -0.430 970.000 1107.550 974.320 ;
      LAYER Pwell ;
        RECT -0.430 966.480 1107.550 970.000 ;
      LAYER Nwell ;
        RECT -0.430 962.160 1107.550 966.480 ;
      LAYER Pwell ;
        RECT -0.430 958.640 1107.550 962.160 ;
      LAYER Nwell ;
        RECT -0.430 954.320 1107.550 958.640 ;
      LAYER Pwell ;
        RECT -0.430 950.800 1107.550 954.320 ;
      LAYER Nwell ;
        RECT -0.430 946.480 1107.550 950.800 ;
      LAYER Pwell ;
        RECT -0.430 942.960 1107.550 946.480 ;
      LAYER Nwell ;
        RECT -0.430 938.640 1107.550 942.960 ;
      LAYER Pwell ;
        RECT -0.430 935.120 1107.550 938.640 ;
      LAYER Nwell ;
        RECT -0.430 930.800 1107.550 935.120 ;
      LAYER Pwell ;
        RECT -0.430 927.280 1107.550 930.800 ;
      LAYER Nwell ;
        RECT -0.430 922.960 1107.550 927.280 ;
      LAYER Pwell ;
        RECT -0.430 919.440 1107.550 922.960 ;
      LAYER Nwell ;
        RECT -0.430 915.120 1107.550 919.440 ;
      LAYER Pwell ;
        RECT -0.430 911.600 1107.550 915.120 ;
      LAYER Nwell ;
        RECT -0.430 907.280 1107.550 911.600 ;
      LAYER Pwell ;
        RECT -0.430 903.760 1107.550 907.280 ;
      LAYER Nwell ;
        RECT -0.430 899.440 1107.550 903.760 ;
      LAYER Pwell ;
        RECT -0.430 895.920 1107.550 899.440 ;
      LAYER Nwell ;
        RECT -0.430 891.600 1107.550 895.920 ;
      LAYER Pwell ;
        RECT -0.430 888.080 1107.550 891.600 ;
      LAYER Nwell ;
        RECT -0.430 883.760 1107.550 888.080 ;
      LAYER Pwell ;
        RECT -0.430 880.240 1107.550 883.760 ;
      LAYER Nwell ;
        RECT -0.430 875.920 1107.550 880.240 ;
      LAYER Pwell ;
        RECT -0.430 872.400 1107.550 875.920 ;
      LAYER Nwell ;
        RECT -0.430 868.080 1107.550 872.400 ;
      LAYER Pwell ;
        RECT -0.430 864.560 1107.550 868.080 ;
      LAYER Nwell ;
        RECT -0.430 860.240 1107.550 864.560 ;
      LAYER Pwell ;
        RECT -0.430 856.720 1107.550 860.240 ;
      LAYER Nwell ;
        RECT -0.430 852.400 1107.550 856.720 ;
      LAYER Pwell ;
        RECT -0.430 848.880 1107.550 852.400 ;
      LAYER Nwell ;
        RECT -0.430 844.560 1107.550 848.880 ;
      LAYER Pwell ;
        RECT -0.430 841.040 1107.550 844.560 ;
      LAYER Nwell ;
        RECT -0.430 836.720 1107.550 841.040 ;
      LAYER Pwell ;
        RECT -0.430 833.200 1107.550 836.720 ;
      LAYER Nwell ;
        RECT -0.430 828.880 1107.550 833.200 ;
      LAYER Pwell ;
        RECT -0.430 825.360 1107.550 828.880 ;
      LAYER Nwell ;
        RECT -0.430 821.040 1107.550 825.360 ;
      LAYER Pwell ;
        RECT -0.430 817.520 1107.550 821.040 ;
      LAYER Nwell ;
        RECT -0.430 813.200 1107.550 817.520 ;
      LAYER Pwell ;
        RECT -0.430 809.680 1107.550 813.200 ;
      LAYER Nwell ;
        RECT -0.430 805.360 1107.550 809.680 ;
      LAYER Pwell ;
        RECT -0.430 801.840 1107.550 805.360 ;
      LAYER Nwell ;
        RECT -0.430 797.520 1107.550 801.840 ;
      LAYER Pwell ;
        RECT -0.430 794.000 1107.550 797.520 ;
      LAYER Nwell ;
        RECT -0.430 789.680 1107.550 794.000 ;
      LAYER Pwell ;
        RECT -0.430 786.160 1107.550 789.680 ;
      LAYER Nwell ;
        RECT -0.430 781.840 1107.550 786.160 ;
      LAYER Pwell ;
        RECT -0.430 778.320 1107.550 781.840 ;
      LAYER Nwell ;
        RECT -0.430 774.000 1107.550 778.320 ;
      LAYER Pwell ;
        RECT -0.430 770.480 1107.550 774.000 ;
      LAYER Nwell ;
        RECT -0.430 766.160 1107.550 770.480 ;
      LAYER Pwell ;
        RECT -0.430 762.640 1107.550 766.160 ;
      LAYER Nwell ;
        RECT -0.430 758.320 1107.550 762.640 ;
      LAYER Pwell ;
        RECT -0.430 754.800 1107.550 758.320 ;
      LAYER Nwell ;
        RECT -0.430 750.480 1107.550 754.800 ;
      LAYER Pwell ;
        RECT -0.430 746.960 1107.550 750.480 ;
      LAYER Nwell ;
        RECT -0.430 742.640 1107.550 746.960 ;
      LAYER Pwell ;
        RECT -0.430 739.120 1107.550 742.640 ;
      LAYER Nwell ;
        RECT -0.430 734.800 1107.550 739.120 ;
      LAYER Pwell ;
        RECT -0.430 731.280 1107.550 734.800 ;
      LAYER Nwell ;
        RECT -0.430 726.960 1107.550 731.280 ;
      LAYER Pwell ;
        RECT -0.430 723.440 1107.550 726.960 ;
      LAYER Nwell ;
        RECT -0.430 719.120 1107.550 723.440 ;
      LAYER Pwell ;
        RECT -0.430 715.600 1107.550 719.120 ;
      LAYER Nwell ;
        RECT -0.430 711.280 1107.550 715.600 ;
      LAYER Pwell ;
        RECT -0.430 707.760 1107.550 711.280 ;
      LAYER Nwell ;
        RECT -0.430 703.440 1107.550 707.760 ;
      LAYER Pwell ;
        RECT -0.430 699.920 1107.550 703.440 ;
      LAYER Nwell ;
        RECT -0.430 695.600 1107.550 699.920 ;
      LAYER Pwell ;
        RECT -0.430 692.080 1107.550 695.600 ;
      LAYER Nwell ;
        RECT -0.430 687.760 1107.550 692.080 ;
      LAYER Pwell ;
        RECT -0.430 684.240 1107.550 687.760 ;
      LAYER Nwell ;
        RECT -0.430 679.920 1107.550 684.240 ;
      LAYER Pwell ;
        RECT -0.430 676.400 1107.550 679.920 ;
      LAYER Nwell ;
        RECT -0.430 672.080 1107.550 676.400 ;
      LAYER Pwell ;
        RECT -0.430 668.560 1107.550 672.080 ;
      LAYER Nwell ;
        RECT -0.430 664.240 1107.550 668.560 ;
      LAYER Pwell ;
        RECT -0.430 660.720 1107.550 664.240 ;
      LAYER Nwell ;
        RECT -0.430 656.400 1107.550 660.720 ;
      LAYER Pwell ;
        RECT -0.430 652.880 1107.550 656.400 ;
      LAYER Nwell ;
        RECT -0.430 648.560 1107.550 652.880 ;
      LAYER Pwell ;
        RECT -0.430 645.040 1107.550 648.560 ;
      LAYER Nwell ;
        RECT -0.430 640.720 1107.550 645.040 ;
      LAYER Pwell ;
        RECT -0.430 637.200 1107.550 640.720 ;
      LAYER Nwell ;
        RECT -0.430 632.880 1107.550 637.200 ;
      LAYER Pwell ;
        RECT -0.430 629.360 1107.550 632.880 ;
      LAYER Nwell ;
        RECT -0.430 625.040 1107.550 629.360 ;
      LAYER Pwell ;
        RECT -0.430 621.520 1107.550 625.040 ;
      LAYER Nwell ;
        RECT -0.430 617.200 1107.550 621.520 ;
      LAYER Pwell ;
        RECT -0.430 613.680 1107.550 617.200 ;
      LAYER Nwell ;
        RECT -0.430 609.360 1107.550 613.680 ;
      LAYER Pwell ;
        RECT -0.430 605.840 1107.550 609.360 ;
      LAYER Nwell ;
        RECT -0.430 601.520 1107.550 605.840 ;
      LAYER Pwell ;
        RECT -0.430 598.000 1107.550 601.520 ;
      LAYER Nwell ;
        RECT -0.430 593.680 1107.550 598.000 ;
      LAYER Pwell ;
        RECT -0.430 590.160 1107.550 593.680 ;
      LAYER Nwell ;
        RECT -0.430 585.840 1107.550 590.160 ;
      LAYER Pwell ;
        RECT -0.430 582.320 1107.550 585.840 ;
      LAYER Nwell ;
        RECT -0.430 578.000 1107.550 582.320 ;
      LAYER Pwell ;
        RECT -0.430 574.480 1107.550 578.000 ;
      LAYER Nwell ;
        RECT -0.430 570.160 1107.550 574.480 ;
      LAYER Pwell ;
        RECT -0.430 566.640 1107.550 570.160 ;
      LAYER Nwell ;
        RECT -0.430 562.320 1107.550 566.640 ;
      LAYER Pwell ;
        RECT -0.430 558.800 1107.550 562.320 ;
      LAYER Nwell ;
        RECT -0.430 554.480 1107.550 558.800 ;
      LAYER Pwell ;
        RECT -0.430 550.960 1107.550 554.480 ;
      LAYER Nwell ;
        RECT -0.430 546.640 1107.550 550.960 ;
      LAYER Pwell ;
        RECT -0.430 543.120 1107.550 546.640 ;
      LAYER Nwell ;
        RECT -0.430 538.800 1107.550 543.120 ;
      LAYER Pwell ;
        RECT -0.430 535.280 1107.550 538.800 ;
      LAYER Nwell ;
        RECT -0.430 530.960 1107.550 535.280 ;
      LAYER Pwell ;
        RECT -0.430 527.440 1107.550 530.960 ;
      LAYER Nwell ;
        RECT -0.430 523.120 1107.550 527.440 ;
      LAYER Pwell ;
        RECT -0.430 519.600 1107.550 523.120 ;
      LAYER Nwell ;
        RECT -0.430 515.280 1107.550 519.600 ;
      LAYER Pwell ;
        RECT -0.430 511.760 1107.550 515.280 ;
      LAYER Nwell ;
        RECT -0.430 507.440 1107.550 511.760 ;
      LAYER Pwell ;
        RECT -0.430 503.920 1107.550 507.440 ;
      LAYER Nwell ;
        RECT -0.430 499.600 1107.550 503.920 ;
      LAYER Pwell ;
        RECT -0.430 496.080 1107.550 499.600 ;
      LAYER Nwell ;
        RECT -0.430 491.760 1107.550 496.080 ;
      LAYER Pwell ;
        RECT -0.430 488.240 1107.550 491.760 ;
      LAYER Nwell ;
        RECT -0.430 483.920 1107.550 488.240 ;
      LAYER Pwell ;
        RECT -0.430 480.400 1107.550 483.920 ;
      LAYER Nwell ;
        RECT -0.430 476.080 1107.550 480.400 ;
      LAYER Pwell ;
        RECT -0.430 472.560 1107.550 476.080 ;
      LAYER Nwell ;
        RECT -0.430 468.240 1107.550 472.560 ;
      LAYER Pwell ;
        RECT -0.430 464.720 1107.550 468.240 ;
      LAYER Nwell ;
        RECT -0.430 460.400 1107.550 464.720 ;
      LAYER Pwell ;
        RECT -0.430 456.880 1107.550 460.400 ;
      LAYER Nwell ;
        RECT -0.430 452.560 1107.550 456.880 ;
      LAYER Pwell ;
        RECT -0.430 449.040 1107.550 452.560 ;
      LAYER Nwell ;
        RECT -0.430 444.720 1107.550 449.040 ;
      LAYER Pwell ;
        RECT -0.430 441.200 1107.550 444.720 ;
      LAYER Nwell ;
        RECT -0.430 436.880 1107.550 441.200 ;
      LAYER Pwell ;
        RECT -0.430 433.360 1107.550 436.880 ;
      LAYER Nwell ;
        RECT -0.430 429.040 1107.550 433.360 ;
      LAYER Pwell ;
        RECT -0.430 425.520 1107.550 429.040 ;
      LAYER Nwell ;
        RECT -0.430 421.200 1107.550 425.520 ;
      LAYER Pwell ;
        RECT -0.430 417.680 1107.550 421.200 ;
      LAYER Nwell ;
        RECT -0.430 413.360 1107.550 417.680 ;
      LAYER Pwell ;
        RECT -0.430 409.840 1107.550 413.360 ;
      LAYER Nwell ;
        RECT -0.430 405.520 1107.550 409.840 ;
      LAYER Pwell ;
        RECT -0.430 402.000 1107.550 405.520 ;
      LAYER Nwell ;
        RECT -0.430 397.680 1107.550 402.000 ;
      LAYER Pwell ;
        RECT -0.430 394.160 1107.550 397.680 ;
      LAYER Nwell ;
        RECT -0.430 389.840 1107.550 394.160 ;
      LAYER Pwell ;
        RECT -0.430 386.320 1107.550 389.840 ;
      LAYER Nwell ;
        RECT -0.430 382.000 1107.550 386.320 ;
      LAYER Pwell ;
        RECT -0.430 378.480 1107.550 382.000 ;
      LAYER Nwell ;
        RECT -0.430 374.160 1107.550 378.480 ;
      LAYER Pwell ;
        RECT -0.430 370.640 1107.550 374.160 ;
      LAYER Nwell ;
        RECT -0.430 366.320 1107.550 370.640 ;
      LAYER Pwell ;
        RECT -0.430 362.800 1107.550 366.320 ;
      LAYER Nwell ;
        RECT -0.430 358.480 1107.550 362.800 ;
      LAYER Pwell ;
        RECT -0.430 354.960 1107.550 358.480 ;
      LAYER Nwell ;
        RECT -0.430 350.640 1107.550 354.960 ;
      LAYER Pwell ;
        RECT -0.430 347.120 1107.550 350.640 ;
      LAYER Nwell ;
        RECT -0.430 342.800 1107.550 347.120 ;
      LAYER Pwell ;
        RECT -0.430 339.280 1107.550 342.800 ;
      LAYER Nwell ;
        RECT -0.430 334.960 1107.550 339.280 ;
      LAYER Pwell ;
        RECT -0.430 331.440 1107.550 334.960 ;
      LAYER Nwell ;
        RECT -0.430 327.120 1107.550 331.440 ;
      LAYER Pwell ;
        RECT -0.430 323.600 1107.550 327.120 ;
      LAYER Nwell ;
        RECT -0.430 319.280 1107.550 323.600 ;
      LAYER Pwell ;
        RECT -0.430 315.760 1107.550 319.280 ;
      LAYER Nwell ;
        RECT -0.430 311.440 1107.550 315.760 ;
      LAYER Pwell ;
        RECT -0.430 307.920 1107.550 311.440 ;
      LAYER Nwell ;
        RECT -0.430 303.600 1107.550 307.920 ;
      LAYER Pwell ;
        RECT -0.430 300.080 1107.550 303.600 ;
      LAYER Nwell ;
        RECT -0.430 295.760 1107.550 300.080 ;
      LAYER Pwell ;
        RECT -0.430 292.240 1107.550 295.760 ;
      LAYER Nwell ;
        RECT -0.430 287.920 1107.550 292.240 ;
      LAYER Pwell ;
        RECT -0.430 284.400 1107.550 287.920 ;
      LAYER Nwell ;
        RECT -0.430 280.080 1107.550 284.400 ;
      LAYER Pwell ;
        RECT -0.430 276.560 1107.550 280.080 ;
      LAYER Nwell ;
        RECT -0.430 272.240 1107.550 276.560 ;
      LAYER Pwell ;
        RECT -0.430 268.720 1107.550 272.240 ;
      LAYER Nwell ;
        RECT -0.430 264.400 1107.550 268.720 ;
      LAYER Pwell ;
        RECT -0.430 260.880 1107.550 264.400 ;
      LAYER Nwell ;
        RECT -0.430 256.560 1107.550 260.880 ;
      LAYER Pwell ;
        RECT -0.430 253.040 1107.550 256.560 ;
      LAYER Nwell ;
        RECT -0.430 248.720 1107.550 253.040 ;
      LAYER Pwell ;
        RECT -0.430 245.200 1107.550 248.720 ;
      LAYER Nwell ;
        RECT -0.430 240.880 1107.550 245.200 ;
      LAYER Pwell ;
        RECT -0.430 237.360 1107.550 240.880 ;
      LAYER Nwell ;
        RECT -0.430 233.040 1107.550 237.360 ;
      LAYER Pwell ;
        RECT -0.430 229.520 1107.550 233.040 ;
      LAYER Nwell ;
        RECT -0.430 225.200 1107.550 229.520 ;
      LAYER Pwell ;
        RECT -0.430 221.680 1107.550 225.200 ;
      LAYER Nwell ;
        RECT -0.430 217.360 1107.550 221.680 ;
      LAYER Pwell ;
        RECT -0.430 213.840 1107.550 217.360 ;
      LAYER Nwell ;
        RECT -0.430 209.520 1107.550 213.840 ;
      LAYER Pwell ;
        RECT -0.430 206.000 1107.550 209.520 ;
      LAYER Nwell ;
        RECT -0.430 201.680 1107.550 206.000 ;
      LAYER Pwell ;
        RECT -0.430 198.160 1107.550 201.680 ;
      LAYER Nwell ;
        RECT -0.430 193.840 1107.550 198.160 ;
      LAYER Pwell ;
        RECT -0.430 190.320 1107.550 193.840 ;
      LAYER Nwell ;
        RECT -0.430 186.000 1107.550 190.320 ;
      LAYER Pwell ;
        RECT -0.430 182.480 1107.550 186.000 ;
      LAYER Nwell ;
        RECT -0.430 178.160 1107.550 182.480 ;
      LAYER Pwell ;
        RECT -0.430 174.640 1107.550 178.160 ;
      LAYER Nwell ;
        RECT -0.430 170.320 1107.550 174.640 ;
      LAYER Pwell ;
        RECT -0.430 166.800 1107.550 170.320 ;
      LAYER Nwell ;
        RECT -0.430 162.480 1107.550 166.800 ;
      LAYER Pwell ;
        RECT -0.430 158.960 1107.550 162.480 ;
      LAYER Nwell ;
        RECT -0.430 154.640 1107.550 158.960 ;
      LAYER Pwell ;
        RECT -0.430 151.120 1107.550 154.640 ;
      LAYER Nwell ;
        RECT -0.430 146.800 1107.550 151.120 ;
      LAYER Pwell ;
        RECT -0.430 143.280 1107.550 146.800 ;
      LAYER Nwell ;
        RECT -0.430 138.960 1107.550 143.280 ;
      LAYER Pwell ;
        RECT -0.430 135.440 1107.550 138.960 ;
      LAYER Nwell ;
        RECT -0.430 131.120 1107.550 135.440 ;
      LAYER Pwell ;
        RECT -0.430 127.600 1107.550 131.120 ;
      LAYER Nwell ;
        RECT -0.430 123.280 1107.550 127.600 ;
      LAYER Pwell ;
        RECT -0.430 119.760 1107.550 123.280 ;
      LAYER Nwell ;
        RECT -0.430 115.440 1107.550 119.760 ;
      LAYER Pwell ;
        RECT -0.430 111.920 1107.550 115.440 ;
      LAYER Nwell ;
        RECT -0.430 107.600 1107.550 111.920 ;
      LAYER Pwell ;
        RECT -0.430 104.080 1107.550 107.600 ;
      LAYER Nwell ;
        RECT -0.430 99.760 1107.550 104.080 ;
      LAYER Pwell ;
        RECT -0.430 96.240 1107.550 99.760 ;
      LAYER Nwell ;
        RECT -0.430 91.920 1107.550 96.240 ;
      LAYER Pwell ;
        RECT -0.430 88.400 1107.550 91.920 ;
      LAYER Nwell ;
        RECT -0.430 84.080 1107.550 88.400 ;
      LAYER Pwell ;
        RECT -0.430 80.560 1107.550 84.080 ;
      LAYER Nwell ;
        RECT -0.430 76.240 1107.550 80.560 ;
      LAYER Pwell ;
        RECT -0.430 72.720 1107.550 76.240 ;
      LAYER Nwell ;
        RECT -0.430 68.400 1107.550 72.720 ;
      LAYER Pwell ;
        RECT -0.430 64.880 1107.550 68.400 ;
      LAYER Nwell ;
        RECT -0.430 60.560 1107.550 64.880 ;
      LAYER Pwell ;
        RECT -0.430 57.040 1107.550 60.560 ;
      LAYER Nwell ;
        RECT -0.430 52.720 1107.550 57.040 ;
      LAYER Pwell ;
        RECT -0.430 49.200 1107.550 52.720 ;
      LAYER Nwell ;
        RECT -0.430 44.880 1107.550 49.200 ;
      LAYER Pwell ;
        RECT -0.430 41.360 1107.550 44.880 ;
      LAYER Nwell ;
        RECT -0.430 37.040 1107.550 41.360 ;
      LAYER Pwell ;
        RECT -0.430 33.520 1107.550 37.040 ;
      LAYER Nwell ;
        RECT -0.430 29.200 1107.550 33.520 ;
      LAYER Pwell ;
        RECT -0.430 25.680 1107.550 29.200 ;
      LAYER Nwell ;
        RECT -0.430 21.360 1107.550 25.680 ;
      LAYER Pwell ;
        RECT -0.430 17.840 1107.550 21.360 ;
      LAYER Nwell ;
        RECT -0.430 13.520 1107.550 17.840 ;
      LAYER Pwell ;
        RECT -0.430 11.330 1107.550 13.520 ;
      LAYER Metal1 ;
        RECT 19.270 1116.600 1107.120 1117.500 ;
        RECT 0.370 1113.880 1107.120 1116.600 ;
        RECT 15.970 1112.680 1107.120 1113.880 ;
        RECT 0.370 1109.960 1107.120 1112.680 ;
        RECT 19.270 1108.760 1107.120 1109.960 ;
        RECT 0.370 1106.040 1107.120 1108.760 ;
        RECT 15.970 1104.840 1107.120 1106.040 ;
        RECT 0.370 1102.120 1107.120 1104.840 ;
        RECT 19.270 1100.920 1107.120 1102.120 ;
        RECT 0.370 1098.200 1107.120 1100.920 ;
        RECT 15.970 1097.000 1107.120 1098.200 ;
        RECT 0.370 1094.280 1107.120 1097.000 ;
        RECT 19.270 1093.080 1107.120 1094.280 ;
        RECT 0.370 1090.360 1107.120 1093.080 ;
        RECT 15.970 1089.160 1107.120 1090.360 ;
        RECT 0.370 1086.440 1107.120 1089.160 ;
        RECT 19.270 1085.240 1107.120 1086.440 ;
        RECT 0.370 1082.520 1107.120 1085.240 ;
        RECT 15.970 1081.320 1107.120 1082.520 ;
        RECT 0.370 1078.600 1107.120 1081.320 ;
        RECT 19.270 1077.400 1107.120 1078.600 ;
        RECT 0.370 1074.680 1107.120 1077.400 ;
        RECT 15.970 1073.480 1107.120 1074.680 ;
        RECT 0.370 1070.760 1107.120 1073.480 ;
        RECT 19.270 1069.560 1107.120 1070.760 ;
        RECT 0.370 1066.840 1107.120 1069.560 ;
        RECT 15.970 1065.640 1107.120 1066.840 ;
        RECT 0.370 1062.920 1107.120 1065.640 ;
        RECT 19.270 1061.720 1107.120 1062.920 ;
        RECT 0.370 1059.000 1107.120 1061.720 ;
        RECT 15.970 1057.800 1107.120 1059.000 ;
        RECT 0.370 1055.080 1107.120 1057.800 ;
        RECT 19.270 1053.880 1107.120 1055.080 ;
        RECT 0.370 1051.160 1107.120 1053.880 ;
        RECT 15.970 1049.960 1107.120 1051.160 ;
        RECT 0.370 1047.240 1107.120 1049.960 ;
        RECT 19.270 1046.040 1107.120 1047.240 ;
        RECT 0.370 1043.320 1107.120 1046.040 ;
        RECT 15.970 1042.120 1107.120 1043.320 ;
        RECT 0.370 1039.400 1107.120 1042.120 ;
        RECT 19.270 1038.200 1107.120 1039.400 ;
        RECT 0.370 1035.480 1107.120 1038.200 ;
        RECT 15.970 1034.280 1107.120 1035.480 ;
        RECT 0.370 1031.560 1107.120 1034.280 ;
        RECT 19.270 1030.360 1107.120 1031.560 ;
        RECT 0.370 1027.640 1107.120 1030.360 ;
        RECT 15.970 1026.440 1107.120 1027.640 ;
        RECT 0.370 1023.720 1107.120 1026.440 ;
        RECT 19.270 1022.520 1107.120 1023.720 ;
        RECT 0.370 1019.800 1107.120 1022.520 ;
        RECT 15.970 1018.600 1107.120 1019.800 ;
        RECT 0.370 1015.880 1107.120 1018.600 ;
        RECT 19.270 1014.680 1107.120 1015.880 ;
        RECT 0.370 1011.960 1107.120 1014.680 ;
        RECT 15.970 1010.760 1107.120 1011.960 ;
        RECT 0.370 1008.040 1107.120 1010.760 ;
        RECT 19.270 1006.840 1107.120 1008.040 ;
        RECT 0.370 1004.120 1107.120 1006.840 ;
        RECT 15.970 1002.920 1107.120 1004.120 ;
        RECT 0.370 1000.200 1107.120 1002.920 ;
        RECT 19.270 999.000 1107.120 1000.200 ;
        RECT 0.370 996.280 1107.120 999.000 ;
        RECT 15.970 995.080 1107.120 996.280 ;
        RECT 0.370 992.360 1107.120 995.080 ;
        RECT 19.270 991.160 1107.120 992.360 ;
        RECT 0.370 988.440 1107.120 991.160 ;
        RECT 15.970 987.240 1107.120 988.440 ;
        RECT 0.370 984.520 1107.120 987.240 ;
        RECT 19.270 983.320 1107.120 984.520 ;
        RECT 0.370 980.600 1107.120 983.320 ;
        RECT 15.970 979.400 1107.120 980.600 ;
        RECT 0.370 976.680 1107.120 979.400 ;
        RECT 19.270 975.480 1107.120 976.680 ;
        RECT 0.370 972.760 1107.120 975.480 ;
        RECT 15.970 971.560 1107.120 972.760 ;
        RECT 0.370 968.840 1107.120 971.560 ;
        RECT 19.270 967.640 1107.120 968.840 ;
        RECT 0.370 964.920 1107.120 967.640 ;
        RECT 15.970 963.720 1107.120 964.920 ;
        RECT 0.370 961.000 1107.120 963.720 ;
        RECT 19.270 959.800 1107.120 961.000 ;
        RECT 0.370 957.080 1107.120 959.800 ;
        RECT 15.970 955.880 1107.120 957.080 ;
        RECT 0.370 953.160 1107.120 955.880 ;
        RECT 19.270 951.960 1107.120 953.160 ;
        RECT 0.370 949.240 1107.120 951.960 ;
        RECT 15.970 948.040 1107.120 949.240 ;
        RECT 0.370 945.320 1107.120 948.040 ;
        RECT 19.270 944.120 1107.120 945.320 ;
        RECT 0.370 941.400 1107.120 944.120 ;
        RECT 15.970 940.200 1107.120 941.400 ;
        RECT 0.370 937.480 1107.120 940.200 ;
        RECT 19.270 936.280 1107.120 937.480 ;
        RECT 0.370 933.560 1107.120 936.280 ;
        RECT 15.970 932.360 1107.120 933.560 ;
        RECT 0.370 929.640 1107.120 932.360 ;
        RECT 19.270 928.440 1107.120 929.640 ;
        RECT 0.370 925.720 1107.120 928.440 ;
        RECT 15.970 924.520 1107.120 925.720 ;
        RECT 0.370 921.800 1107.120 924.520 ;
        RECT 19.270 920.600 1107.120 921.800 ;
        RECT 0.370 917.880 1107.120 920.600 ;
        RECT 15.970 916.680 1107.120 917.880 ;
        RECT 0.370 913.960 1107.120 916.680 ;
        RECT 19.270 912.760 1107.120 913.960 ;
        RECT 0.370 910.040 1107.120 912.760 ;
        RECT 15.970 908.840 1107.120 910.040 ;
        RECT 0.370 906.120 1107.120 908.840 ;
        RECT 19.270 904.920 1107.120 906.120 ;
        RECT 0.370 902.200 1107.120 904.920 ;
        RECT 15.970 901.000 1107.120 902.200 ;
        RECT 0.370 898.280 1107.120 901.000 ;
        RECT 19.270 897.080 1107.120 898.280 ;
        RECT 0.370 894.360 1107.120 897.080 ;
        RECT 15.970 893.160 1107.120 894.360 ;
        RECT 0.370 890.440 1107.120 893.160 ;
        RECT 19.270 889.240 1107.120 890.440 ;
        RECT 0.370 886.520 1107.120 889.240 ;
        RECT 15.970 885.320 1107.120 886.520 ;
        RECT 0.370 882.600 1107.120 885.320 ;
        RECT 19.270 881.400 1107.120 882.600 ;
        RECT 0.370 878.680 1107.120 881.400 ;
        RECT 15.970 877.480 1107.120 878.680 ;
        RECT 0.370 874.760 1107.120 877.480 ;
        RECT 19.270 873.560 1107.120 874.760 ;
        RECT 0.370 870.840 1107.120 873.560 ;
        RECT 15.970 869.640 1107.120 870.840 ;
        RECT 0.370 866.920 1107.120 869.640 ;
        RECT 19.270 865.720 1107.120 866.920 ;
        RECT 0.370 863.000 1107.120 865.720 ;
        RECT 15.970 861.800 1107.120 863.000 ;
        RECT 0.370 859.080 1107.120 861.800 ;
        RECT 19.270 857.880 1107.120 859.080 ;
        RECT 0.370 855.160 1107.120 857.880 ;
        RECT 15.970 853.960 1107.120 855.160 ;
        RECT 0.370 851.240 1107.120 853.960 ;
        RECT 19.270 850.040 1107.120 851.240 ;
        RECT 0.370 847.320 1107.120 850.040 ;
        RECT 15.970 846.120 1107.120 847.320 ;
        RECT 0.370 843.400 1107.120 846.120 ;
        RECT 19.270 842.200 1107.120 843.400 ;
        RECT 0.370 839.480 1107.120 842.200 ;
        RECT 15.970 838.280 1107.120 839.480 ;
        RECT 0.370 835.560 1107.120 838.280 ;
        RECT 19.270 834.360 1107.120 835.560 ;
        RECT 0.370 831.640 1107.120 834.360 ;
        RECT 15.970 830.440 1107.120 831.640 ;
        RECT 0.370 827.720 1107.120 830.440 ;
        RECT 19.270 826.520 1107.120 827.720 ;
        RECT 0.370 823.800 1107.120 826.520 ;
        RECT 15.970 822.600 1107.120 823.800 ;
        RECT 0.370 819.880 1107.120 822.600 ;
        RECT 19.270 818.680 1107.120 819.880 ;
        RECT 0.370 815.960 1107.120 818.680 ;
        RECT 15.970 814.760 1107.120 815.960 ;
        RECT 0.370 812.040 1107.120 814.760 ;
        RECT 19.270 810.840 1107.120 812.040 ;
        RECT 0.370 808.120 1107.120 810.840 ;
        RECT 15.970 806.920 1107.120 808.120 ;
        RECT 0.370 804.200 1107.120 806.920 ;
        RECT 19.270 803.000 1107.120 804.200 ;
        RECT 0.370 800.280 1107.120 803.000 ;
        RECT 15.970 799.080 1107.120 800.280 ;
        RECT 0.370 796.360 1107.120 799.080 ;
        RECT 19.270 795.160 1107.120 796.360 ;
        RECT 0.370 792.440 1107.120 795.160 ;
        RECT 15.970 791.240 1107.120 792.440 ;
        RECT 0.370 788.520 1107.120 791.240 ;
        RECT 19.270 787.320 1107.120 788.520 ;
        RECT 0.370 784.600 1107.120 787.320 ;
        RECT 15.970 783.400 1107.120 784.600 ;
        RECT 0.370 780.680 1107.120 783.400 ;
        RECT 19.270 779.480 1107.120 780.680 ;
        RECT 0.370 776.760 1107.120 779.480 ;
        RECT 15.970 775.560 1107.120 776.760 ;
        RECT 0.370 772.840 1107.120 775.560 ;
        RECT 19.270 771.640 1107.120 772.840 ;
        RECT 0.370 768.920 1107.120 771.640 ;
        RECT 15.970 767.720 1107.120 768.920 ;
        RECT 0.370 765.000 1107.120 767.720 ;
        RECT 19.270 763.800 1107.120 765.000 ;
        RECT 0.370 761.080 1107.120 763.800 ;
        RECT 15.970 759.880 1107.120 761.080 ;
        RECT 0.370 757.160 1107.120 759.880 ;
        RECT 19.270 755.960 1107.120 757.160 ;
        RECT 0.370 753.240 1107.120 755.960 ;
        RECT 15.970 752.040 1107.120 753.240 ;
        RECT 0.370 749.320 1107.120 752.040 ;
        RECT 19.270 748.120 1107.120 749.320 ;
        RECT 0.370 745.400 1107.120 748.120 ;
        RECT 15.970 744.200 1107.120 745.400 ;
        RECT 0.370 741.480 1107.120 744.200 ;
        RECT 19.270 740.280 1107.120 741.480 ;
        RECT 0.370 737.560 1107.120 740.280 ;
        RECT 15.970 736.360 1107.120 737.560 ;
        RECT 0.370 733.640 1107.120 736.360 ;
        RECT 19.270 732.440 1107.120 733.640 ;
        RECT 0.370 729.720 1107.120 732.440 ;
        RECT 15.970 728.520 1107.120 729.720 ;
        RECT 0.370 725.800 1107.120 728.520 ;
        RECT 19.270 724.600 1107.120 725.800 ;
        RECT 0.370 721.880 1107.120 724.600 ;
        RECT 15.970 720.680 1107.120 721.880 ;
        RECT 0.370 717.960 1107.120 720.680 ;
        RECT 19.270 716.760 1107.120 717.960 ;
        RECT 0.370 714.040 1107.120 716.760 ;
        RECT 15.970 712.840 1107.120 714.040 ;
        RECT 0.370 710.120 1107.120 712.840 ;
        RECT 19.270 708.920 1107.120 710.120 ;
        RECT 0.370 706.200 1107.120 708.920 ;
        RECT 15.970 705.000 1107.120 706.200 ;
        RECT 0.370 702.280 1107.120 705.000 ;
        RECT 19.270 701.080 1107.120 702.280 ;
        RECT 0.370 698.360 1107.120 701.080 ;
        RECT 15.970 697.160 1107.120 698.360 ;
        RECT 0.370 694.440 1107.120 697.160 ;
        RECT 19.270 693.240 1107.120 694.440 ;
        RECT 0.370 690.520 1107.120 693.240 ;
        RECT 15.970 689.320 1107.120 690.520 ;
        RECT 0.370 686.600 1107.120 689.320 ;
        RECT 19.270 685.400 1107.120 686.600 ;
        RECT 0.370 682.680 1107.120 685.400 ;
        RECT 15.970 681.480 1107.120 682.680 ;
        RECT 0.370 678.760 1107.120 681.480 ;
        RECT 19.270 677.560 1107.120 678.760 ;
        RECT 0.370 674.840 1107.120 677.560 ;
        RECT 15.970 673.640 1107.120 674.840 ;
        RECT 0.370 670.920 1107.120 673.640 ;
        RECT 19.270 669.720 1107.120 670.920 ;
        RECT 0.370 667.000 1107.120 669.720 ;
        RECT 15.970 665.800 1107.120 667.000 ;
        RECT 0.370 663.080 1107.120 665.800 ;
        RECT 19.270 661.880 1107.120 663.080 ;
        RECT 0.370 659.160 1107.120 661.880 ;
        RECT 15.970 657.960 1107.120 659.160 ;
        RECT 0.370 655.240 1107.120 657.960 ;
        RECT 19.270 654.040 1107.120 655.240 ;
        RECT 0.370 651.320 1107.120 654.040 ;
        RECT 15.970 650.120 1107.120 651.320 ;
        RECT 0.370 647.400 1107.120 650.120 ;
        RECT 19.270 646.200 1107.120 647.400 ;
        RECT 0.370 643.480 1107.120 646.200 ;
        RECT 15.970 642.280 1107.120 643.480 ;
        RECT 0.370 639.560 1107.120 642.280 ;
        RECT 19.270 638.360 1107.120 639.560 ;
        RECT 0.370 635.640 1107.120 638.360 ;
        RECT 15.970 634.440 1107.120 635.640 ;
        RECT 0.370 631.720 1107.120 634.440 ;
        RECT 19.270 630.520 1107.120 631.720 ;
        RECT 0.370 627.800 1107.120 630.520 ;
        RECT 15.970 626.600 1107.120 627.800 ;
        RECT 0.370 623.880 1107.120 626.600 ;
        RECT 19.270 622.680 1107.120 623.880 ;
        RECT 0.370 619.960 1107.120 622.680 ;
        RECT 15.970 618.760 1107.120 619.960 ;
        RECT 0.370 616.040 1107.120 618.760 ;
        RECT 19.270 614.840 1107.120 616.040 ;
        RECT 0.370 612.120 1107.120 614.840 ;
        RECT 15.970 610.920 1107.120 612.120 ;
        RECT 0.370 608.200 1107.120 610.920 ;
        RECT 19.270 607.000 1107.120 608.200 ;
        RECT 0.370 604.280 1107.120 607.000 ;
        RECT 15.970 603.080 1107.120 604.280 ;
        RECT 0.370 600.360 1107.120 603.080 ;
        RECT 19.270 599.160 1107.120 600.360 ;
        RECT 0.370 596.440 1107.120 599.160 ;
        RECT 15.970 595.240 1107.120 596.440 ;
        RECT 0.370 592.520 1107.120 595.240 ;
        RECT 19.270 591.320 1107.120 592.520 ;
        RECT 0.370 588.600 1107.120 591.320 ;
        RECT 15.970 587.400 1107.120 588.600 ;
        RECT 0.370 584.680 1107.120 587.400 ;
        RECT 19.270 583.480 1107.120 584.680 ;
        RECT 0.370 580.760 1107.120 583.480 ;
        RECT 15.970 579.560 1107.120 580.760 ;
        RECT 0.370 576.840 1107.120 579.560 ;
        RECT 19.270 575.640 1107.120 576.840 ;
        RECT 0.370 572.920 1107.120 575.640 ;
        RECT 15.970 571.720 1107.120 572.920 ;
        RECT 0.370 569.000 1107.120 571.720 ;
        RECT 19.270 567.800 1107.120 569.000 ;
        RECT 0.370 565.080 1107.120 567.800 ;
        RECT 15.970 563.880 1107.120 565.080 ;
        RECT 0.370 561.160 1107.120 563.880 ;
        RECT 19.270 559.960 1107.120 561.160 ;
        RECT 0.370 557.240 1107.120 559.960 ;
        RECT 15.970 556.040 1107.120 557.240 ;
        RECT 0.370 553.320 1107.120 556.040 ;
        RECT 19.270 552.120 1107.120 553.320 ;
        RECT 0.370 549.400 1107.120 552.120 ;
        RECT 15.970 548.200 1107.120 549.400 ;
        RECT 0.370 545.480 1107.120 548.200 ;
        RECT 19.270 544.280 1107.120 545.480 ;
        RECT 0.370 541.560 1107.120 544.280 ;
        RECT 15.970 540.360 1107.120 541.560 ;
        RECT 0.370 537.640 1107.120 540.360 ;
        RECT 19.270 536.440 1107.120 537.640 ;
        RECT 0.370 533.720 1107.120 536.440 ;
        RECT 15.970 532.520 1107.120 533.720 ;
        RECT 0.370 529.800 1107.120 532.520 ;
        RECT 19.270 528.600 1107.120 529.800 ;
        RECT 0.370 525.880 1107.120 528.600 ;
        RECT 15.970 524.680 1107.120 525.880 ;
        RECT 0.370 521.960 1107.120 524.680 ;
        RECT 19.270 520.760 1107.120 521.960 ;
        RECT 0.370 518.040 1107.120 520.760 ;
        RECT 15.970 516.840 1107.120 518.040 ;
        RECT 0.370 514.120 1107.120 516.840 ;
        RECT 19.270 512.920 1107.120 514.120 ;
        RECT 0.370 510.200 1107.120 512.920 ;
        RECT 15.970 509.000 1107.120 510.200 ;
        RECT 0.370 506.280 1107.120 509.000 ;
        RECT 19.270 505.080 1107.120 506.280 ;
        RECT 0.370 502.360 1107.120 505.080 ;
        RECT 15.970 501.160 1107.120 502.360 ;
        RECT 0.370 498.440 1107.120 501.160 ;
        RECT 19.270 497.240 1107.120 498.440 ;
        RECT 0.370 494.520 1107.120 497.240 ;
        RECT 15.970 493.320 1107.120 494.520 ;
        RECT 0.370 490.600 1107.120 493.320 ;
        RECT 19.270 489.400 1107.120 490.600 ;
        RECT 0.370 486.680 1107.120 489.400 ;
        RECT 15.970 485.480 1107.120 486.680 ;
        RECT 0.370 482.760 1107.120 485.480 ;
        RECT 19.270 481.560 1107.120 482.760 ;
        RECT 0.370 478.840 1107.120 481.560 ;
        RECT 15.970 477.640 1107.120 478.840 ;
        RECT 0.370 474.920 1107.120 477.640 ;
        RECT 19.270 473.720 1107.120 474.920 ;
        RECT 0.370 471.000 1107.120 473.720 ;
        RECT 15.970 469.800 1107.120 471.000 ;
        RECT 0.370 467.080 1107.120 469.800 ;
        RECT 19.270 465.880 1107.120 467.080 ;
        RECT 0.370 463.160 1107.120 465.880 ;
        RECT 15.970 461.960 1107.120 463.160 ;
        RECT 0.370 459.240 1107.120 461.960 ;
        RECT 19.270 458.040 1107.120 459.240 ;
        RECT 0.370 455.320 1107.120 458.040 ;
        RECT 15.970 454.120 1107.120 455.320 ;
        RECT 0.370 451.400 1107.120 454.120 ;
        RECT 19.270 450.200 1107.120 451.400 ;
        RECT 0.370 447.480 1107.120 450.200 ;
        RECT 15.970 446.280 1107.120 447.480 ;
        RECT 0.370 443.560 1107.120 446.280 ;
        RECT 19.270 442.360 1107.120 443.560 ;
        RECT 0.370 439.640 1107.120 442.360 ;
        RECT 15.970 438.440 1107.120 439.640 ;
        RECT 0.370 435.720 1107.120 438.440 ;
        RECT 19.270 434.520 1107.120 435.720 ;
        RECT 0.370 431.800 1107.120 434.520 ;
        RECT 15.970 430.600 1107.120 431.800 ;
        RECT 0.370 427.880 1107.120 430.600 ;
        RECT 19.270 426.680 1107.120 427.880 ;
        RECT 0.370 423.960 1107.120 426.680 ;
        RECT 15.970 422.760 1107.120 423.960 ;
        RECT 0.370 420.040 1107.120 422.760 ;
        RECT 19.270 418.840 1107.120 420.040 ;
        RECT 0.370 416.120 1107.120 418.840 ;
        RECT 15.970 414.920 1107.120 416.120 ;
        RECT 0.370 412.200 1107.120 414.920 ;
        RECT 19.270 411.000 1107.120 412.200 ;
        RECT 0.370 408.280 1107.120 411.000 ;
        RECT 15.970 407.080 1107.120 408.280 ;
        RECT 0.370 404.360 1107.120 407.080 ;
        RECT 19.270 403.160 1107.120 404.360 ;
        RECT 0.370 400.440 1107.120 403.160 ;
        RECT 15.970 399.240 1107.120 400.440 ;
        RECT 0.370 396.520 1107.120 399.240 ;
        RECT 19.270 395.320 1107.120 396.520 ;
        RECT 0.370 392.600 1107.120 395.320 ;
        RECT 15.970 391.400 1107.120 392.600 ;
        RECT 0.370 388.680 1107.120 391.400 ;
        RECT 19.270 387.480 1107.120 388.680 ;
        RECT 0.370 384.760 1107.120 387.480 ;
        RECT 15.970 383.560 1107.120 384.760 ;
        RECT 0.370 380.840 1107.120 383.560 ;
        RECT 19.270 379.640 1107.120 380.840 ;
        RECT 0.370 376.920 1107.120 379.640 ;
        RECT 15.970 375.720 1107.120 376.920 ;
        RECT 0.370 373.000 1107.120 375.720 ;
        RECT 19.270 371.800 1107.120 373.000 ;
        RECT 0.370 369.080 1107.120 371.800 ;
        RECT 11.390 367.880 1107.120 369.080 ;
        RECT 0.370 365.160 1107.120 367.880 ;
        RECT 19.270 363.960 1107.120 365.160 ;
        RECT 0.370 361.240 1107.120 363.960 ;
        RECT 15.970 360.040 1107.120 361.240 ;
        RECT 0.370 357.320 1107.120 360.040 ;
        RECT 19.270 356.120 1107.120 357.320 ;
        RECT 0.370 353.400 1107.120 356.120 ;
        RECT 15.970 352.200 1107.120 353.400 ;
        RECT 0.370 349.480 1107.120 352.200 ;
        RECT 19.270 348.280 1107.120 349.480 ;
        RECT 0.370 345.560 1107.120 348.280 ;
        RECT 15.970 344.360 1107.120 345.560 ;
        RECT 0.370 341.640 1107.120 344.360 ;
        RECT 19.270 340.440 1107.120 341.640 ;
        RECT 0.370 337.720 1107.120 340.440 ;
        RECT 15.970 336.520 1107.120 337.720 ;
        RECT 0.370 333.800 1107.120 336.520 ;
        RECT 19.270 332.600 1107.120 333.800 ;
        RECT 0.370 329.880 1107.120 332.600 ;
        RECT 15.970 328.680 1107.120 329.880 ;
        RECT 0.370 325.960 1107.120 328.680 ;
        RECT 19.270 324.760 1107.120 325.960 ;
        RECT 0.370 322.040 1107.120 324.760 ;
        RECT 15.970 320.840 1107.120 322.040 ;
        RECT 0.370 318.120 1107.120 320.840 ;
        RECT 19.270 316.920 1107.120 318.120 ;
        RECT 0.370 314.200 1107.120 316.920 ;
        RECT 15.970 313.000 1107.120 314.200 ;
        RECT 0.370 310.280 1107.120 313.000 ;
        RECT 19.270 309.080 1107.120 310.280 ;
        RECT 0.370 306.360 1107.120 309.080 ;
        RECT 15.970 305.160 1107.120 306.360 ;
        RECT 0.370 302.440 1107.120 305.160 ;
        RECT 19.270 301.240 1107.120 302.440 ;
        RECT 0.370 298.520 1107.120 301.240 ;
        RECT 15.970 297.320 1107.120 298.520 ;
        RECT 0.370 294.600 1107.120 297.320 ;
        RECT 19.270 293.400 1107.120 294.600 ;
        RECT 0.370 290.680 1107.120 293.400 ;
        RECT 15.970 289.480 1107.120 290.680 ;
        RECT 0.370 286.760 1107.120 289.480 ;
        RECT 19.270 285.560 1107.120 286.760 ;
        RECT 0.370 282.840 1107.120 285.560 ;
        RECT 15.970 281.640 1107.120 282.840 ;
        RECT 0.370 278.920 1107.120 281.640 ;
        RECT 19.270 277.720 1107.120 278.920 ;
        RECT 0.370 275.000 1107.120 277.720 ;
        RECT 15.970 273.800 1107.120 275.000 ;
        RECT 0.370 271.080 1107.120 273.800 ;
        RECT 19.270 269.880 1107.120 271.080 ;
        RECT 0.370 267.160 1107.120 269.880 ;
        RECT 15.970 265.960 1107.120 267.160 ;
        RECT 0.370 263.240 1107.120 265.960 ;
        RECT 19.270 262.040 1107.120 263.240 ;
        RECT 0.370 259.320 1107.120 262.040 ;
        RECT 15.970 258.120 1107.120 259.320 ;
        RECT 0.370 255.400 1107.120 258.120 ;
        RECT 19.270 254.200 1107.120 255.400 ;
        RECT 0.370 251.480 1107.120 254.200 ;
        RECT 15.970 250.280 1107.120 251.480 ;
        RECT 0.370 247.560 1107.120 250.280 ;
        RECT 19.270 246.360 1107.120 247.560 ;
        RECT 0.370 243.640 1107.120 246.360 ;
        RECT 15.970 242.440 1107.120 243.640 ;
        RECT 0.370 239.720 1107.120 242.440 ;
        RECT 19.270 238.520 1107.120 239.720 ;
        RECT 0.370 235.800 1107.120 238.520 ;
        RECT 15.970 234.600 1107.120 235.800 ;
        RECT 0.370 231.880 1107.120 234.600 ;
        RECT 19.270 230.680 1107.120 231.880 ;
        RECT 0.370 227.960 1107.120 230.680 ;
        RECT 15.970 226.760 1107.120 227.960 ;
        RECT 0.370 224.040 1107.120 226.760 ;
        RECT 19.270 222.840 1107.120 224.040 ;
        RECT 0.370 220.120 1107.120 222.840 ;
        RECT 15.970 218.920 1107.120 220.120 ;
        RECT 0.370 216.200 1107.120 218.920 ;
        RECT 19.270 215.000 1107.120 216.200 ;
        RECT 0.370 212.280 1107.120 215.000 ;
        RECT 15.970 211.080 1107.120 212.280 ;
        RECT 0.370 208.360 1107.120 211.080 ;
        RECT 19.270 207.160 1107.120 208.360 ;
        RECT 0.370 204.440 1107.120 207.160 ;
        RECT 15.970 203.240 1107.120 204.440 ;
        RECT 0.370 200.520 1107.120 203.240 ;
        RECT 19.270 199.320 1107.120 200.520 ;
        RECT 0.370 196.600 1107.120 199.320 ;
        RECT 15.970 195.400 1107.120 196.600 ;
        RECT 0.370 192.680 1107.120 195.400 ;
        RECT 19.270 191.480 1107.120 192.680 ;
        RECT 0.370 188.760 1107.120 191.480 ;
        RECT 15.970 187.560 1107.120 188.760 ;
        RECT 0.370 184.840 1107.120 187.560 ;
        RECT 19.270 183.640 1107.120 184.840 ;
        RECT 0.370 180.920 1107.120 183.640 ;
        RECT 15.970 179.720 1107.120 180.920 ;
        RECT 0.370 177.000 1107.120 179.720 ;
        RECT 19.270 175.800 1107.120 177.000 ;
        RECT 0.370 173.080 1107.120 175.800 ;
        RECT 15.970 171.880 1107.120 173.080 ;
        RECT 0.370 169.160 1107.120 171.880 ;
        RECT 19.270 167.960 1107.120 169.160 ;
        RECT 0.370 165.240 1107.120 167.960 ;
        RECT 15.970 164.040 1107.120 165.240 ;
        RECT 0.370 161.320 1107.120 164.040 ;
        RECT 19.270 160.120 1107.120 161.320 ;
        RECT 0.370 157.400 1107.120 160.120 ;
        RECT 15.970 156.200 1107.120 157.400 ;
        RECT 0.370 153.480 1107.120 156.200 ;
        RECT 19.270 152.280 1107.120 153.480 ;
        RECT 0.370 149.560 1107.120 152.280 ;
        RECT 15.970 148.360 1107.120 149.560 ;
        RECT 0.370 145.640 1107.120 148.360 ;
        RECT 19.270 144.440 1107.120 145.640 ;
        RECT 0.370 141.720 1107.120 144.440 ;
        RECT 15.970 140.520 1107.120 141.720 ;
        RECT 0.370 137.800 1107.120 140.520 ;
        RECT 19.270 136.600 1107.120 137.800 ;
        RECT 0.370 133.880 1107.120 136.600 ;
        RECT 15.970 132.680 1107.120 133.880 ;
        RECT 0.370 129.960 1107.120 132.680 ;
        RECT 19.270 128.760 1107.120 129.960 ;
        RECT 0.370 126.040 1107.120 128.760 ;
        RECT 15.970 124.840 1107.120 126.040 ;
        RECT 0.370 122.120 1107.120 124.840 ;
        RECT 19.270 120.920 1107.120 122.120 ;
        RECT 0.370 118.200 1107.120 120.920 ;
        RECT 15.970 117.000 1107.120 118.200 ;
        RECT 0.370 114.280 1107.120 117.000 ;
        RECT 19.270 113.080 1107.120 114.280 ;
        RECT 0.370 110.360 1107.120 113.080 ;
        RECT 15.970 109.160 1107.120 110.360 ;
        RECT 0.370 106.440 1107.120 109.160 ;
        RECT 19.270 105.240 1107.120 106.440 ;
        RECT 0.370 102.520 1107.120 105.240 ;
        RECT 15.970 101.320 1107.120 102.520 ;
        RECT 0.370 98.600 1107.120 101.320 ;
        RECT 19.270 97.400 1107.120 98.600 ;
        RECT 0.370 94.680 1107.120 97.400 ;
        RECT 15.970 93.480 1107.120 94.680 ;
        RECT 0.370 90.760 1107.120 93.480 ;
        RECT 19.270 89.560 1107.120 90.760 ;
        RECT 0.370 86.840 1107.120 89.560 ;
        RECT 15.970 85.640 1107.120 86.840 ;
        RECT 0.370 82.920 1107.120 85.640 ;
        RECT 19.270 81.720 1107.120 82.920 ;
        RECT 0.370 79.000 1107.120 81.720 ;
        RECT 15.970 77.800 1107.120 79.000 ;
        RECT 0.370 75.080 1107.120 77.800 ;
        RECT 19.270 73.880 1107.120 75.080 ;
        RECT 0.370 71.160 1107.120 73.880 ;
        RECT 15.970 69.960 1107.120 71.160 ;
        RECT 0.370 67.240 1107.120 69.960 ;
        RECT 19.270 66.040 1107.120 67.240 ;
        RECT 0.370 63.320 1107.120 66.040 ;
        RECT 15.970 62.120 1107.120 63.320 ;
        RECT 0.370 59.400 1107.120 62.120 ;
        RECT 19.270 58.200 1107.120 59.400 ;
        RECT 0.370 55.480 1107.120 58.200 ;
        RECT 15.970 54.280 1107.120 55.480 ;
        RECT 0.370 51.560 1107.120 54.280 ;
        RECT 19.270 50.360 1107.120 51.560 ;
        RECT 0.370 47.640 1107.120 50.360 ;
        RECT 15.970 46.440 1107.120 47.640 ;
        RECT 0.370 43.720 1107.120 46.440 ;
        RECT 19.270 42.520 1107.120 43.720 ;
        RECT 0.370 39.800 1107.120 42.520 ;
        RECT 15.970 38.600 1107.120 39.800 ;
        RECT 0.370 35.880 1107.120 38.600 ;
        RECT 19.270 34.680 1107.120 35.880 ;
        RECT 0.370 31.960 1107.120 34.680 ;
        RECT 15.970 30.760 1107.120 31.960 ;
        RECT 0.370 28.040 1107.120 30.760 ;
        RECT 19.270 26.840 1107.120 28.040 ;
        RECT 0.370 24.120 1107.120 26.840 ;
        RECT 15.970 22.920 1107.120 24.120 ;
        RECT 0.370 20.200 1107.120 22.920 ;
        RECT 19.270 19.000 1107.120 20.200 ;
        RECT 0.370 16.280 1107.120 19.000 ;
        RECT 15.970 15.080 1107.120 16.280 ;
        RECT 0.370 12.360 1107.120 15.080 ;
        RECT 19.270 11.460 1107.120 12.360 ;
      LAYER Metal2 ;
        RECT 0.140 1116.640 53.460 1117.390 ;
        RECT 54.620 1116.640 154.260 1117.390 ;
        RECT 155.420 1116.640 255.060 1117.390 ;
        RECT 256.220 1116.640 355.860 1117.390 ;
        RECT 357.020 1116.640 557.460 1117.390 ;
        RECT 558.620 1116.640 759.060 1117.390 ;
        RECT 760.220 1116.640 960.660 1117.390 ;
        RECT 961.820 1116.640 1095.480 1117.390 ;
        RECT 0.140 11.570 1095.480 1116.640 ;
      LAYER Metal3 ;
        RECT 0.090 1032.380 1095.530 1117.340 ;
        RECT 0.860 1031.220 1095.530 1032.380 ;
        RECT 0.090 937.180 1095.530 1031.220 ;
        RECT 0.860 936.020 1095.530 937.180 ;
        RECT 0.090 841.980 1095.530 936.020 ;
        RECT 0.860 840.820 1095.530 841.980 ;
        RECT 0.090 746.780 1095.530 840.820 ;
        RECT 0.860 745.620 1095.530 746.780 ;
        RECT 0.090 651.580 1095.530 745.620 ;
        RECT 0.860 650.420 1095.530 651.580 ;
        RECT 0.090 561.980 1095.530 650.420 ;
        RECT 0.860 560.820 1095.530 561.980 ;
        RECT 0.090 556.380 1095.530 560.820 ;
        RECT 0.860 555.220 1095.530 556.380 ;
        RECT 0.090 466.780 1095.530 555.220 ;
        RECT 0.860 465.620 1095.530 466.780 ;
        RECT 0.090 371.580 1095.530 465.620 ;
        RECT 0.860 370.420 1095.530 371.580 ;
        RECT 0.090 276.380 1095.530 370.420 ;
        RECT 0.860 275.220 1095.530 276.380 ;
        RECT 0.090 181.180 1095.530 275.220 ;
        RECT 0.860 180.020 1095.530 181.180 ;
        RECT 0.090 11.620 1095.530 180.020 ;
      LAYER Metal4 ;
        RECT 18.060 398.810 18.520 1055.510 ;
        RECT 20.720 398.810 168.820 1055.510 ;
        RECT 171.020 398.810 172.120 1055.510 ;
        RECT 174.320 398.810 322.420 1055.510 ;
        RECT 324.620 398.810 325.720 1055.510 ;
        RECT 327.920 398.810 476.020 1055.510 ;
        RECT 478.220 398.810 479.320 1055.510 ;
        RECT 481.520 398.810 629.620 1055.510 ;
        RECT 631.820 398.810 632.920 1055.510 ;
        RECT 635.120 398.810 682.500 1055.510 ;
  END
END wrapper
END LIBRARY

